# Generated deterministically by seda-macro-lef-normalizer-v1; recipe orfs-ng45-fakeram-metal3-coupledl2-pg-v1.
VERSION 5.8 ;
BUSBITCHARS "[]" ;
DIVIDERCHAR "/" ;

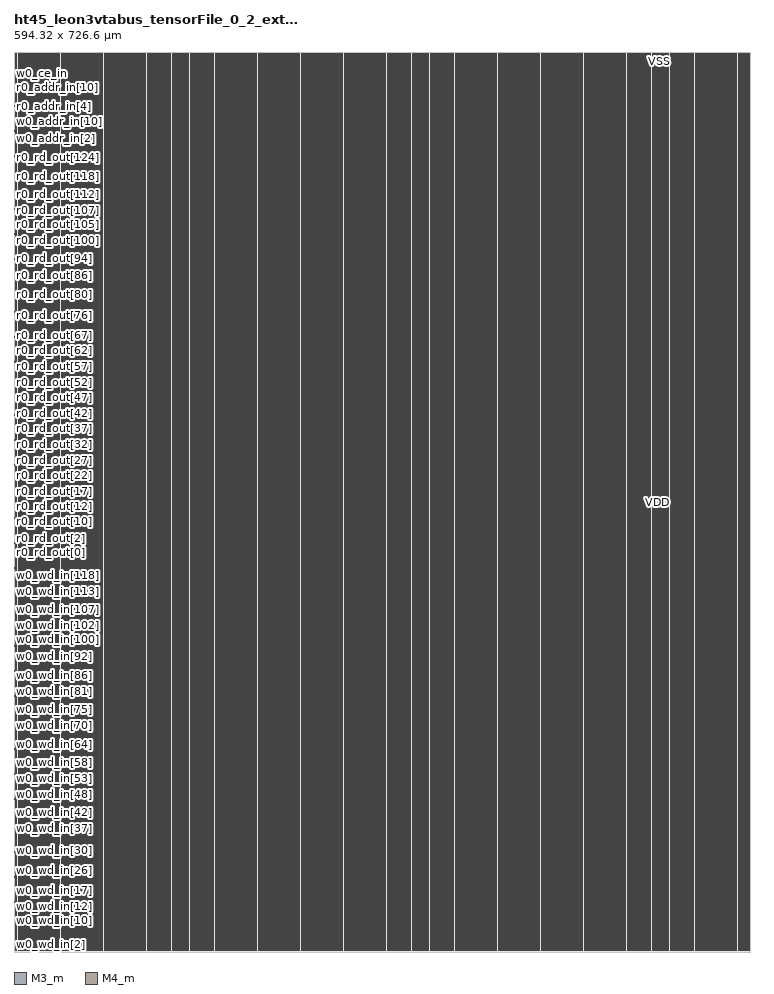
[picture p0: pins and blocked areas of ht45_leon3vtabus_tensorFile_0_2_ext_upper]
MACRO ht45_leon3vtabus_tensorFile_0_2_ext_upper
  FOREIGN ht45_leon3vtabus_tensorFile_0_2_ext_upper 0 0 ;
  CLASS COVER ;
  ORIGIN 0 0 ;
  SIZE 594.32 BY 726.6 ;
  SYMMETRY X Y R90 ;
  PIN w0_wd_in[0]
    DIRECTION INPUT ;
    USE SIGNAL ;
    SHAPE ABUTMENT ;
    PORT
      LAYER M3_m ;
      RECT 0 0.035 0.07 0.105 ;
    END
  END w0_wd_in[0]
  PIN w0_wd_in[1]
    DIRECTION INPUT ;
    USE SIGNAL ;
    SHAPE ABUTMENT ;
    PORT
      LAYER M3_m ;
      RECT 0 2.555 0.07 2.625 ;
    END
  END w0_wd_in[1]
  PIN w0_wd_in[2]
    DIRECTION INPUT ;
    USE SIGNAL ;
    SHAPE ABUTMENT ;
    PORT
      LAYER M3_m ;
      RECT 0 5.075 0.07 5.145 ;
    END
  END w0_wd_in[2]
  PIN w0_wd_in[3]
    DIRECTION INPUT ;
    USE SIGNAL ;
    SHAPE ABUTMENT ;
    PORT
      LAYER M3_m ;
      RECT 0 7.595 0.07 7.665 ;
    END
  END w0_wd_in[3]
  PIN w0_wd_in[4]
    DIRECTION INPUT ;
    USE SIGNAL ;
    SHAPE ABUTMENT ;
    PORT
      LAYER M3_m ;
      RECT 0 10.115 0.07 10.185 ;
    END
  END w0_wd_in[4]
  PIN w0_wd_in[5]
    DIRECTION INPUT ;
    USE SIGNAL ;
    SHAPE ABUTMENT ;
    PORT
      LAYER M3_m ;
      RECT 0 12.635 0.07 12.705 ;
    END
  END w0_wd_in[5]
  PIN w0_wd_in[6]
    DIRECTION INPUT ;
    USE SIGNAL ;
    SHAPE ABUTMENT ;
    PORT
      LAYER M3_m ;
      RECT 0 15.155 0.07 15.225 ;
    END
  END w0_wd_in[6]
  PIN w0_wd_in[7]
    DIRECTION INPUT ;
    USE SIGNAL ;
    SHAPE ABUTMENT ;
    PORT
      LAYER M3_m ;
      RECT 0 17.675 0.07 17.745 ;
    END
  END w0_wd_in[7]
  PIN w0_wd_in[8]
    DIRECTION INPUT ;
    USE SIGNAL ;
    SHAPE ABUTMENT ;
    PORT
      LAYER M3_m ;
      RECT 0 20.195 0.07 20.265 ;
    END
  END w0_wd_in[8]
  PIN w0_wd_in[9]
    DIRECTION INPUT ;
    USE SIGNAL ;
    SHAPE ABUTMENT ;
    PORT
      LAYER M3_m ;
      RECT 0 22.715 0.07 22.785 ;
    END
  END w0_wd_in[9]
  PIN w0_wd_in[10]
    DIRECTION INPUT ;
    USE SIGNAL ;
    SHAPE ABUTMENT ;
    PORT
      LAYER M3_m ;
      RECT 0 25.235 0.07 25.305 ;
    END
  END w0_wd_in[10]
  PIN w0_wd_in[11]
    DIRECTION INPUT ;
    USE SIGNAL ;
    SHAPE ABUTMENT ;
    PORT
      LAYER M3_m ;
      RECT 0 27.755 0.07 27.825 ;
    END
  END w0_wd_in[11]
  PIN w0_wd_in[12]
    DIRECTION INPUT ;
    USE SIGNAL ;
    SHAPE ABUTMENT ;
    PORT
      LAYER M3_m ;
      RECT 0 30.275 0.07 30.345 ;
    END
  END w0_wd_in[12]
  PIN w0_wd_in[13]
    DIRECTION INPUT ;
    USE SIGNAL ;
    SHAPE ABUTMENT ;
    PORT
      LAYER M3_m ;
      RECT 0 32.795 0.07 32.865 ;
    END
  END w0_wd_in[13]
  PIN w0_wd_in[14]
    DIRECTION INPUT ;
    USE SIGNAL ;
    SHAPE ABUTMENT ;
    PORT
      LAYER M3_m ;
      RECT 0 35.315 0.07 35.385 ;
    END
  END w0_wd_in[14]
  PIN w0_wd_in[15]
    DIRECTION INPUT ;
    USE SIGNAL ;
    SHAPE ABUTMENT ;
    PORT
      LAYER M3_m ;
      RECT 0 37.835 0.07 37.905 ;
    END
  END w0_wd_in[15]
  PIN w0_wd_in[16]
    DIRECTION INPUT ;
    USE SIGNAL ;
    SHAPE ABUTMENT ;
    PORT
      LAYER M3_m ;
      RECT 0 40.355 0.07 40.425 ;
    END
  END w0_wd_in[16]
  PIN w0_wd_in[17]
    DIRECTION INPUT ;
    USE SIGNAL ;
    SHAPE ABUTMENT ;
    PORT
      LAYER M3_m ;
      RECT 0 42.875 0.07 42.945 ;
    END
  END w0_wd_in[17]
  PIN w0_wd_in[18]
    DIRECTION INPUT ;
    USE SIGNAL ;
    SHAPE ABUTMENT ;
    PORT
      LAYER M3_m ;
      RECT 0 45.395 0.07 45.465 ;
    END
  END w0_wd_in[18]
  PIN w0_wd_in[19]
    DIRECTION INPUT ;
    USE SIGNAL ;
    SHAPE ABUTMENT ;
    PORT
      LAYER M3_m ;
      RECT 0 47.915 0.07 47.985 ;
    END
  END w0_wd_in[19]
  PIN w0_wd_in[20]
    DIRECTION INPUT ;
    USE SIGNAL ;
    SHAPE ABUTMENT ;
    PORT
      LAYER M3_m ;
      RECT 0 50.435 0.07 50.505 ;
    END
  END w0_wd_in[20]
  PIN w0_wd_in[21]
    DIRECTION INPUT ;
    USE SIGNAL ;
    SHAPE ABUTMENT ;
    PORT
      LAYER M3_m ;
      RECT 0 52.955 0.07 53.025 ;
    END
  END w0_wd_in[21]
  PIN w0_wd_in[22]
    DIRECTION INPUT ;
    USE SIGNAL ;
    SHAPE ABUTMENT ;
    PORT
      LAYER M3_m ;
      RECT 0 55.475 0.07 55.545 ;
    END
  END w0_wd_in[22]
  PIN w0_wd_in[23]
    DIRECTION INPUT ;
    USE SIGNAL ;
    SHAPE ABUTMENT ;
    PORT
      LAYER M3_m ;
      RECT 0 57.995 0.07 58.065 ;
    END
  END w0_wd_in[23]
  PIN w0_wd_in[24]
    DIRECTION INPUT ;
    USE SIGNAL ;
    SHAPE ABUTMENT ;
    PORT
      LAYER M3_m ;
      RECT 0 60.515 0.07 60.585 ;
    END
  END w0_wd_in[24]
  PIN w0_wd_in[25]
    DIRECTION INPUT ;
    USE SIGNAL ;
    SHAPE ABUTMENT ;
    PORT
      LAYER M3_m ;
      RECT 0 63.035 0.07 63.105 ;
    END
  END w0_wd_in[25]
  PIN w0_wd_in[26]
    DIRECTION INPUT ;
    USE SIGNAL ;
    SHAPE ABUTMENT ;
    PORT
      LAYER M3_m ;
      RECT 0 65.555 0.07 65.625 ;
    END
  END w0_wd_in[26]
  PIN w0_wd_in[27]
    DIRECTION INPUT ;
    USE SIGNAL ;
    SHAPE ABUTMENT ;
    PORT
      LAYER M3_m ;
      RECT 0 68.075 0.07 68.145 ;
    END
  END w0_wd_in[27]
  PIN w0_wd_in[28]
    DIRECTION INPUT ;
    USE SIGNAL ;
    SHAPE ABUTMENT ;
    PORT
      LAYER M3_m ;
      RECT 0 70.595 0.07 70.665 ;
    END
  END w0_wd_in[28]
  PIN w0_wd_in[29]
    DIRECTION INPUT ;
    USE SIGNAL ;
    SHAPE ABUTMENT ;
    PORT
      LAYER M3_m ;
      RECT 0 73.115 0.07 73.185 ;
    END
  END w0_wd_in[29]
  PIN w0_wd_in[30]
    DIRECTION INPUT ;
    USE SIGNAL ;
    SHAPE ABUTMENT ;
    PORT
      LAYER M3_m ;
      RECT 0 75.635 0.07 75.705 ;
    END
  END w0_wd_in[30]
  PIN w0_wd_in[31]
    DIRECTION INPUT ;
    USE SIGNAL ;
    SHAPE ABUTMENT ;
    PORT
      LAYER M3_m ;
      RECT 0 78.155 0.07 78.225 ;
    END
  END w0_wd_in[31]
  PIN w0_wd_in[32]
    DIRECTION INPUT ;
    USE SIGNAL ;
    SHAPE ABUTMENT ;
    PORT
      LAYER M3_m ;
      RECT 0 80.675 0.07 80.745 ;
    END
  END w0_wd_in[32]
  PIN w0_wd_in[33]
    DIRECTION INPUT ;
    USE SIGNAL ;
    SHAPE ABUTMENT ;
    PORT
      LAYER M3_m ;
      RECT 0 83.195 0.07 83.265 ;
    END
  END w0_wd_in[33]
  PIN w0_wd_in[34]
    DIRECTION INPUT ;
    USE SIGNAL ;
    SHAPE ABUTMENT ;
    PORT
      LAYER M3_m ;
      RECT 0 85.715 0.07 85.785 ;
    END
  END w0_wd_in[34]
  PIN w0_wd_in[35]
    DIRECTION INPUT ;
    USE SIGNAL ;
    SHAPE ABUTMENT ;
    PORT
      LAYER M3_m ;
      RECT 0 88.235 0.07 88.305 ;
    END
  END w0_wd_in[35]
  PIN w0_wd_in[36]
    DIRECTION INPUT ;
    USE SIGNAL ;
    SHAPE ABUTMENT ;
    PORT
      LAYER M3_m ;
      RECT 0 90.755 0.07 90.825 ;
    END
  END w0_wd_in[36]
  PIN w0_wd_in[37]
    DIRECTION INPUT ;
    USE SIGNAL ;
    SHAPE ABUTMENT ;
    PORT
      LAYER M3_m ;
      RECT 0 93.275 0.07 93.345 ;
    END
  END w0_wd_in[37]
  PIN w0_wd_in[38]
    DIRECTION INPUT ;
    USE SIGNAL ;
    SHAPE ABUTMENT ;
    PORT
      LAYER M3_m ;
      RECT 0 95.795 0.07 95.865 ;
    END
  END w0_wd_in[38]
  PIN w0_wd_in[39]
    DIRECTION INPUT ;
    USE SIGNAL ;
    SHAPE ABUTMENT ;
    PORT
      LAYER M3_m ;
      RECT 0 98.315 0.07 98.385 ;
    END
  END w0_wd_in[39]
  PIN w0_wd_in[40]
    DIRECTION INPUT ;
    USE SIGNAL ;
    SHAPE ABUTMENT ;
    PORT
      LAYER M3_m ;
      RECT 0 100.835 0.07 100.905 ;
    END
  END w0_wd_in[40]
  PIN w0_wd_in[41]
    DIRECTION INPUT ;
    USE SIGNAL ;
    SHAPE ABUTMENT ;
    PORT
      LAYER M3_m ;
      RECT 0 103.355 0.07 103.425 ;
    END
  END w0_wd_in[41]
  PIN w0_wd_in[42]
    DIRECTION INPUT ;
    USE SIGNAL ;
    SHAPE ABUTMENT ;
    PORT
      LAYER M3_m ;
      RECT 0 105.875 0.07 105.945 ;
    END
  END w0_wd_in[42]
  PIN w0_wd_in[43]
    DIRECTION INPUT ;
    USE SIGNAL ;
    SHAPE ABUTMENT ;
    PORT
      LAYER M3_m ;
      RECT 0 108.395 0.07 108.465 ;
    END
  END w0_wd_in[43]
  PIN w0_wd_in[44]
    DIRECTION INPUT ;
    USE SIGNAL ;
    SHAPE ABUTMENT ;
    PORT
      LAYER M3_m ;
      RECT 0 110.915 0.07 110.985 ;
    END
  END w0_wd_in[44]
  PIN w0_wd_in[45]
    DIRECTION INPUT ;
    USE SIGNAL ;
    SHAPE ABUTMENT ;
    PORT
      LAYER M3_m ;
      RECT 0 113.435 0.07 113.505 ;
    END
  END w0_wd_in[45]
  PIN w0_wd_in[46]
    DIRECTION INPUT ;
    USE SIGNAL ;
    SHAPE ABUTMENT ;
    PORT
      LAYER M3_m ;
      RECT 0 115.955 0.07 116.025 ;
    END
  END w0_wd_in[46]
  PIN w0_wd_in[47]
    DIRECTION INPUT ;
    USE SIGNAL ;
    SHAPE ABUTMENT ;
    PORT
      LAYER M3_m ;
      RECT 0 118.475 0.07 118.545 ;
    END
  END w0_wd_in[47]
  PIN w0_wd_in[48]
    DIRECTION INPUT ;
    USE SIGNAL ;
    SHAPE ABUTMENT ;
    PORT
      LAYER M3_m ;
      RECT 0 120.995 0.07 121.065 ;
    END
  END w0_wd_in[48]
  PIN w0_wd_in[49]
    DIRECTION INPUT ;
    USE SIGNAL ;
    SHAPE ABUTMENT ;
    PORT
      LAYER M3_m ;
      RECT 0 123.515 0.07 123.585 ;
    END
  END w0_wd_in[49]
  PIN w0_wd_in[50]
    DIRECTION INPUT ;
    USE SIGNAL ;
    SHAPE ABUTMENT ;
    PORT
      LAYER M3_m ;
      RECT 0 126.035 0.07 126.105 ;
    END
  END w0_wd_in[50]
  PIN w0_wd_in[51]
    DIRECTION INPUT ;
    USE SIGNAL ;
    SHAPE ABUTMENT ;
    PORT
      LAYER M3_m ;
      RECT 0 128.555 0.07 128.625 ;
    END
  END w0_wd_in[51]
  PIN w0_wd_in[52]
    DIRECTION INPUT ;
    USE SIGNAL ;
    SHAPE ABUTMENT ;
    PORT
      LAYER M3_m ;
      RECT 0 131.075 0.07 131.145 ;
    END
  END w0_wd_in[52]
  PIN w0_wd_in[53]
    DIRECTION INPUT ;
    USE SIGNAL ;
    SHAPE ABUTMENT ;
    PORT
      LAYER M3_m ;
      RECT 0 133.595 0.07 133.665 ;
    END
  END w0_wd_in[53]
  PIN w0_wd_in[54]
    DIRECTION INPUT ;
    USE SIGNAL ;
    SHAPE ABUTMENT ;
    PORT
      LAYER M3_m ;
      RECT 0 136.115 0.07 136.185 ;
    END
  END w0_wd_in[54]
  PIN w0_wd_in[55]
    DIRECTION INPUT ;
    USE SIGNAL ;
    SHAPE ABUTMENT ;
    PORT
      LAYER M3_m ;
      RECT 0 138.635 0.07 138.705 ;
    END
  END w0_wd_in[55]
  PIN w0_wd_in[56]
    DIRECTION INPUT ;
    USE SIGNAL ;
    SHAPE ABUTMENT ;
    PORT
      LAYER M3_m ;
      RECT 0 141.155 0.07 141.225 ;
    END
  END w0_wd_in[56]
  PIN w0_wd_in[57]
    DIRECTION INPUT ;
    USE SIGNAL ;
    SHAPE ABUTMENT ;
    PORT
      LAYER M3_m ;
      RECT 0 143.675 0.07 143.745 ;
    END
  END w0_wd_in[57]
  PIN w0_wd_in[58]
    DIRECTION INPUT ;
    USE SIGNAL ;
    SHAPE ABUTMENT ;
    PORT
      LAYER M3_m ;
      RECT 0 146.195 0.07 146.265 ;
    END
  END w0_wd_in[58]
  PIN w0_wd_in[59]
    DIRECTION INPUT ;
    USE SIGNAL ;
    SHAPE ABUTMENT ;
    PORT
      LAYER M3_m ;
      RECT 0 148.715 0.07 148.785 ;
    END
  END w0_wd_in[59]
  PIN w0_wd_in[60]
    DIRECTION INPUT ;
    USE SIGNAL ;
    SHAPE ABUTMENT ;
    PORT
      LAYER M3_m ;
      RECT 0 151.235 0.07 151.305 ;
    END
  END w0_wd_in[60]
  PIN w0_wd_in[61]
    DIRECTION INPUT ;
    USE SIGNAL ;
    SHAPE ABUTMENT ;
    PORT
      LAYER M3_m ;
      RECT 0 153.755 0.07 153.825 ;
    END
  END w0_wd_in[61]
  PIN w0_wd_in[62]
    DIRECTION INPUT ;
    USE SIGNAL ;
    SHAPE ABUTMENT ;
    PORT
      LAYER M3_m ;
      RECT 0 156.275 0.07 156.345 ;
    END
  END w0_wd_in[62]
  PIN w0_wd_in[63]
    DIRECTION INPUT ;
    USE SIGNAL ;
    SHAPE ABUTMENT ;
    PORT
      LAYER M3_m ;
      RECT 0 158.795 0.07 158.865 ;
    END
  END w0_wd_in[63]
  PIN w0_wd_in[64]
    DIRECTION INPUT ;
    USE SIGNAL ;
    SHAPE ABUTMENT ;
    PORT
      LAYER M3_m ;
      RECT 0 161.315 0.07 161.385 ;
    END
  END w0_wd_in[64]
  PIN w0_wd_in[65]
    DIRECTION INPUT ;
    USE SIGNAL ;
    SHAPE ABUTMENT ;
    PORT
      LAYER M3_m ;
      RECT 0 163.835 0.07 163.905 ;
    END
  END w0_wd_in[65]
  PIN w0_wd_in[66]
    DIRECTION INPUT ;
    USE SIGNAL ;
    SHAPE ABUTMENT ;
    PORT
      LAYER M3_m ;
      RECT 0 166.355 0.07 166.425 ;
    END
  END w0_wd_in[66]
  PIN w0_wd_in[67]
    DIRECTION INPUT ;
    USE SIGNAL ;
    SHAPE ABUTMENT ;
    PORT
      LAYER M3_m ;
      RECT 0 168.875 0.07 168.945 ;
    END
  END w0_wd_in[67]
  PIN w0_wd_in[68]
    DIRECTION INPUT ;
    USE SIGNAL ;
    SHAPE ABUTMENT ;
    PORT
      LAYER M3_m ;
      RECT 0 171.395 0.07 171.465 ;
    END
  END w0_wd_in[68]
  PIN w0_wd_in[69]
    DIRECTION INPUT ;
    USE SIGNAL ;
    SHAPE ABUTMENT ;
    PORT
      LAYER M3_m ;
      RECT 0 173.915 0.07 173.985 ;
    END
  END w0_wd_in[69]
  PIN w0_wd_in[70]
    DIRECTION INPUT ;
    USE SIGNAL ;
    SHAPE ABUTMENT ;
    PORT
      LAYER M3_m ;
      RECT 0 176.435 0.07 176.505 ;
    END
  END w0_wd_in[70]
  PIN w0_wd_in[71]
    DIRECTION INPUT ;
    USE SIGNAL ;
    SHAPE ABUTMENT ;
    PORT
      LAYER M3_m ;
      RECT 0 178.955 0.07 179.025 ;
    END
  END w0_wd_in[71]
  PIN w0_wd_in[72]
    DIRECTION INPUT ;
    USE SIGNAL ;
    SHAPE ABUTMENT ;
    PORT
      LAYER M3_m ;
      RECT 0 181.475 0.07 181.545 ;
    END
  END w0_wd_in[72]
  PIN w0_wd_in[73]
    DIRECTION INPUT ;
    USE SIGNAL ;
    SHAPE ABUTMENT ;
    PORT
      LAYER M3_m ;
      RECT 0 183.995 0.07 184.065 ;
    END
  END w0_wd_in[73]
  PIN w0_wd_in[74]
    DIRECTION INPUT ;
    USE SIGNAL ;
    SHAPE ABUTMENT ;
    PORT
      LAYER M3_m ;
      RECT 0 186.515 0.07 186.585 ;
    END
  END w0_wd_in[74]
  PIN w0_wd_in[75]
    DIRECTION INPUT ;
    USE SIGNAL ;
    SHAPE ABUTMENT ;
    PORT
      LAYER M3_m ;
      RECT 0 189.035 0.07 189.105 ;
    END
  END w0_wd_in[75]
  PIN w0_wd_in[76]
    DIRECTION INPUT ;
    USE SIGNAL ;
    SHAPE ABUTMENT ;
    PORT
      LAYER M3_m ;
      RECT 0 191.555 0.07 191.625 ;
    END
  END w0_wd_in[76]
  PIN w0_wd_in[77]
    DIRECTION INPUT ;
    USE SIGNAL ;
    SHAPE ABUTMENT ;
    PORT
      LAYER M3_m ;
      RECT 0 194.075 0.07 194.145 ;
    END
  END w0_wd_in[77]
  PIN w0_wd_in[78]
    DIRECTION INPUT ;
    USE SIGNAL ;
    SHAPE ABUTMENT ;
    PORT
      LAYER M3_m ;
      RECT 0 196.595 0.07 196.665 ;
    END
  END w0_wd_in[78]
  PIN w0_wd_in[79]
    DIRECTION INPUT ;
    USE SIGNAL ;
    SHAPE ABUTMENT ;
    PORT
      LAYER M3_m ;
      RECT 0 199.115 0.07 199.185 ;
    END
  END w0_wd_in[79]
  PIN w0_wd_in[80]
    DIRECTION INPUT ;
    USE SIGNAL ;
    SHAPE ABUTMENT ;
    PORT
      LAYER M3_m ;
      RECT 0 201.635 0.07 201.705 ;
    END
  END w0_wd_in[80]
  PIN w0_wd_in[81]
    DIRECTION INPUT ;
    USE SIGNAL ;
    SHAPE ABUTMENT ;
    PORT
      LAYER M3_m ;
      RECT 0 204.155 0.07 204.225 ;
    END
  END w0_wd_in[81]
  PIN w0_wd_in[82]
    DIRECTION INPUT ;
    USE SIGNAL ;
    SHAPE ABUTMENT ;
    PORT
      LAYER M3_m ;
      RECT 0 206.675 0.07 206.745 ;
    END
  END w0_wd_in[82]
  PIN w0_wd_in[83]
    DIRECTION INPUT ;
    USE SIGNAL ;
    SHAPE ABUTMENT ;
    PORT
      LAYER M3_m ;
      RECT 0 209.195 0.07 209.265 ;
    END
  END w0_wd_in[83]
  PIN w0_wd_in[84]
    DIRECTION INPUT ;
    USE SIGNAL ;
    SHAPE ABUTMENT ;
    PORT
      LAYER M3_m ;
      RECT 0 211.715 0.07 211.785 ;
    END
  END w0_wd_in[84]
  PIN w0_wd_in[85]
    DIRECTION INPUT ;
    USE SIGNAL ;
    SHAPE ABUTMENT ;
    PORT
      LAYER M3_m ;
      RECT 0 214.235 0.07 214.305 ;
    END
  END w0_wd_in[85]
  PIN w0_wd_in[86]
    DIRECTION INPUT ;
    USE SIGNAL ;
    SHAPE ABUTMENT ;
    PORT
      LAYER M3_m ;
      RECT 0 216.755 0.07 216.825 ;
    END
  END w0_wd_in[86]
  PIN w0_wd_in[87]
    DIRECTION INPUT ;
    USE SIGNAL ;
    SHAPE ABUTMENT ;
    PORT
      LAYER M3_m ;
      RECT 0 219.275 0.07 219.345 ;
    END
  END w0_wd_in[87]
  PIN w0_wd_in[88]
    DIRECTION INPUT ;
    USE SIGNAL ;
    SHAPE ABUTMENT ;
    PORT
      LAYER M3_m ;
      RECT 0 221.795 0.07 221.865 ;
    END
  END w0_wd_in[88]
  PIN w0_wd_in[89]
    DIRECTION INPUT ;
    USE SIGNAL ;
    SHAPE ABUTMENT ;
    PORT
      LAYER M3_m ;
      RECT 0 224.315 0.07 224.385 ;
    END
  END w0_wd_in[89]
  PIN w0_wd_in[90]
    DIRECTION INPUT ;
    USE SIGNAL ;
    SHAPE ABUTMENT ;
    PORT
      LAYER M3_m ;
      RECT 0 226.835 0.07 226.905 ;
    END
  END w0_wd_in[90]
  PIN w0_wd_in[91]
    DIRECTION INPUT ;
    USE SIGNAL ;
    SHAPE ABUTMENT ;
    PORT
      LAYER M3_m ;
      RECT 0 229.355 0.07 229.425 ;
    END
  END w0_wd_in[91]
  PIN w0_wd_in[92]
    DIRECTION INPUT ;
    USE SIGNAL ;
    SHAPE ABUTMENT ;
    PORT
      LAYER M3_m ;
      RECT 0 231.875 0.07 231.945 ;
    END
  END w0_wd_in[92]
  PIN w0_wd_in[93]
    DIRECTION INPUT ;
    USE SIGNAL ;
    SHAPE ABUTMENT ;
    PORT
      LAYER M3_m ;
      RECT 0 234.395 0.07 234.465 ;
    END
  END w0_wd_in[93]
  PIN w0_wd_in[94]
    DIRECTION INPUT ;
    USE SIGNAL ;
    SHAPE ABUTMENT ;
    PORT
      LAYER M3_m ;
      RECT 0 236.915 0.07 236.985 ;
    END
  END w0_wd_in[94]
  PIN w0_wd_in[95]
    DIRECTION INPUT ;
    USE SIGNAL ;
    SHAPE ABUTMENT ;
    PORT
      LAYER M3_m ;
      RECT 0 239.435 0.07 239.505 ;
    END
  END w0_wd_in[95]
  PIN w0_wd_in[96]
    DIRECTION INPUT ;
    USE SIGNAL ;
    SHAPE ABUTMENT ;
    PORT
      LAYER M3_m ;
      RECT 0 241.955 0.07 242.025 ;
    END
  END w0_wd_in[96]
  PIN w0_wd_in[97]
    DIRECTION INPUT ;
    USE SIGNAL ;
    SHAPE ABUTMENT ;
    PORT
      LAYER M3_m ;
      RECT 0 244.475 0.07 244.545 ;
    END
  END w0_wd_in[97]
  PIN w0_wd_in[98]
    DIRECTION INPUT ;
    USE SIGNAL ;
    SHAPE ABUTMENT ;
    PORT
      LAYER M3_m ;
      RECT 0 246.995 0.07 247.065 ;
    END
  END w0_wd_in[98]
  PIN w0_wd_in[99]
    DIRECTION INPUT ;
    USE SIGNAL ;
    SHAPE ABUTMENT ;
    PORT
      LAYER M3_m ;
      RECT 0 249.515 0.07 249.585 ;
    END
  END w0_wd_in[99]
  PIN w0_wd_in[100]
    DIRECTION INPUT ;
    USE SIGNAL ;
    SHAPE ABUTMENT ;
    PORT
      LAYER M3_m ;
      RECT 0 252.035 0.07 252.105 ;
    END
  END w0_wd_in[100]
  PIN w0_wd_in[101]
    DIRECTION INPUT ;
    USE SIGNAL ;
    SHAPE ABUTMENT ;
    PORT
      LAYER M3_m ;
      RECT 0 254.555 0.07 254.625 ;
    END
  END w0_wd_in[101]
  PIN w0_wd_in[102]
    DIRECTION INPUT ;
    USE SIGNAL ;
    SHAPE ABUTMENT ;
    PORT
      LAYER M3_m ;
      RECT 0 257.075 0.07 257.145 ;
    END
  END w0_wd_in[102]
  PIN w0_wd_in[103]
    DIRECTION INPUT ;
    USE SIGNAL ;
    SHAPE ABUTMENT ;
    PORT
      LAYER M3_m ;
      RECT 0 259.595 0.07 259.665 ;
    END
  END w0_wd_in[103]
  PIN w0_wd_in[104]
    DIRECTION INPUT ;
    USE SIGNAL ;
    SHAPE ABUTMENT ;
    PORT
      LAYER M3_m ;
      RECT 0 262.115 0.07 262.185 ;
    END
  END w0_wd_in[104]
  PIN w0_wd_in[105]
    DIRECTION INPUT ;
    USE SIGNAL ;
    SHAPE ABUTMENT ;
    PORT
      LAYER M3_m ;
      RECT 0 264.635 0.07 264.705 ;
    END
  END w0_wd_in[105]
  PIN w0_wd_in[106]
    DIRECTION INPUT ;
    USE SIGNAL ;
    SHAPE ABUTMENT ;
    PORT
      LAYER M3_m ;
      RECT 0 267.155 0.07 267.225 ;
    END
  END w0_wd_in[106]
  PIN w0_wd_in[107]
    DIRECTION INPUT ;
    USE SIGNAL ;
    SHAPE ABUTMENT ;
    PORT
      LAYER M3_m ;
      RECT 0 269.675 0.07 269.745 ;
    END
  END w0_wd_in[107]
  PIN w0_wd_in[108]
    DIRECTION INPUT ;
    USE SIGNAL ;
    SHAPE ABUTMENT ;
    PORT
      LAYER M3_m ;
      RECT 0 272.195 0.07 272.265 ;
    END
  END w0_wd_in[108]
  PIN w0_wd_in[109]
    DIRECTION INPUT ;
    USE SIGNAL ;
    SHAPE ABUTMENT ;
    PORT
      LAYER M3_m ;
      RECT 0 274.715 0.07 274.785 ;
    END
  END w0_wd_in[109]
  PIN w0_wd_in[110]
    DIRECTION INPUT ;
    USE SIGNAL ;
    SHAPE ABUTMENT ;
    PORT
      LAYER M3_m ;
      RECT 0 277.235 0.07 277.305 ;
    END
  END w0_wd_in[110]
  PIN w0_wd_in[111]
    DIRECTION INPUT ;
    USE SIGNAL ;
    SHAPE ABUTMENT ;
    PORT
      LAYER M3_m ;
      RECT 0 279.755 0.07 279.825 ;
    END
  END w0_wd_in[111]
  PIN w0_wd_in[112]
    DIRECTION INPUT ;
    USE SIGNAL ;
    SHAPE ABUTMENT ;
    PORT
      LAYER M3_m ;
      RECT 0 282.275 0.07 282.345 ;
    END
  END w0_wd_in[112]
  PIN w0_wd_in[113]
    DIRECTION INPUT ;
    USE SIGNAL ;
    SHAPE ABUTMENT ;
    PORT
      LAYER M3_m ;
      RECT 0 284.795 0.07 284.865 ;
    END
  END w0_wd_in[113]
  PIN w0_wd_in[114]
    DIRECTION INPUT ;
    USE SIGNAL ;
    SHAPE ABUTMENT ;
    PORT
      LAYER M3_m ;
      RECT 0 287.315 0.07 287.385 ;
    END
  END w0_wd_in[114]
  PIN w0_wd_in[115]
    DIRECTION INPUT ;
    USE SIGNAL ;
    SHAPE ABUTMENT ;
    PORT
      LAYER M3_m ;
      RECT 0 289.835 0.07 289.905 ;
    END
  END w0_wd_in[115]
  PIN w0_wd_in[116]
    DIRECTION INPUT ;
    USE SIGNAL ;
    SHAPE ABUTMENT ;
    PORT
      LAYER M3_m ;
      RECT 0 292.355 0.07 292.425 ;
    END
  END w0_wd_in[116]
  PIN w0_wd_in[117]
    DIRECTION INPUT ;
    USE SIGNAL ;
    SHAPE ABUTMENT ;
    PORT
      LAYER M3_m ;
      RECT 0 294.875 0.07 294.945 ;
    END
  END w0_wd_in[117]
  PIN w0_wd_in[118]
    DIRECTION INPUT ;
    USE SIGNAL ;
    SHAPE ABUTMENT ;
    PORT
      LAYER M3_m ;
      RECT 0 297.395 0.07 297.465 ;
    END
  END w0_wd_in[118]
  PIN w0_wd_in[119]
    DIRECTION INPUT ;
    USE SIGNAL ;
    SHAPE ABUTMENT ;
    PORT
      LAYER M3_m ;
      RECT 0 299.915 0.07 299.985 ;
    END
  END w0_wd_in[119]
  PIN w0_wd_in[120]
    DIRECTION INPUT ;
    USE SIGNAL ;
    SHAPE ABUTMENT ;
    PORT
      LAYER M3_m ;
      RECT 0 302.435 0.07 302.505 ;
    END
  END w0_wd_in[120]
  PIN w0_wd_in[121]
    DIRECTION INPUT ;
    USE SIGNAL ;
    SHAPE ABUTMENT ;
    PORT
      LAYER M3_m ;
      RECT 0 304.955 0.07 305.025 ;
    END
  END w0_wd_in[121]
  PIN w0_wd_in[122]
    DIRECTION INPUT ;
    USE SIGNAL ;
    SHAPE ABUTMENT ;
    PORT
      LAYER M3_m ;
      RECT 0 307.475 0.07 307.545 ;
    END
  END w0_wd_in[122]
  PIN w0_wd_in[123]
    DIRECTION INPUT ;
    USE SIGNAL ;
    SHAPE ABUTMENT ;
    PORT
      LAYER M3_m ;
      RECT 0 309.995 0.07 310.065 ;
    END
  END w0_wd_in[123]
  PIN w0_wd_in[124]
    DIRECTION INPUT ;
    USE SIGNAL ;
    SHAPE ABUTMENT ;
    PORT
      LAYER M3_m ;
      RECT 0 312.515 0.07 312.585 ;
    END
  END w0_wd_in[124]
  PIN w0_wd_in[125]
    DIRECTION INPUT ;
    USE SIGNAL ;
    SHAPE ABUTMENT ;
    PORT
      LAYER M3_m ;
      RECT 0 315.035 0.07 315.105 ;
    END
  END w0_wd_in[125]
  PIN w0_wd_in[126]
    DIRECTION INPUT ;
    USE SIGNAL ;
    SHAPE ABUTMENT ;
    PORT
      LAYER M3_m ;
      RECT 0 317.555 0.07 317.625 ;
    END
  END w0_wd_in[126]
  PIN w0_wd_in[127]
    DIRECTION INPUT ;
    USE SIGNAL ;
    SHAPE ABUTMENT ;
    PORT
      LAYER M3_m ;
      RECT 0 320.075 0.07 320.145 ;
    END
  END w0_wd_in[127]
  PIN r0_rd_out[0]
    DIRECTION OUTPUT ;
    USE SIGNAL ;
    SHAPE ABUTMENT ;
    PORT
      LAYER M3_m ;
      RECT 0 322.595 0.07 322.665 ;
    END
  END r0_rd_out[0]
  PIN r0_rd_out[1]
    DIRECTION OUTPUT ;
    USE SIGNAL ;
    SHAPE ABUTMENT ;
    PORT
      LAYER M3_m ;
      RECT 0 325.115 0.07 325.185 ;
    END
  END r0_rd_out[1]
  PIN r0_rd_out[2]
    DIRECTION OUTPUT ;
    USE SIGNAL ;
    SHAPE ABUTMENT ;
    PORT
      LAYER M3_m ;
      RECT 0 327.635 0.07 327.705 ;
    END
  END r0_rd_out[2]
  PIN r0_rd_out[3]
    DIRECTION OUTPUT ;
    USE SIGNAL ;
    SHAPE ABUTMENT ;
    PORT
      LAYER M3_m ;
      RECT 0 330.155 0.07 330.225 ;
    END
  END r0_rd_out[3]
  PIN r0_rd_out[4]
    DIRECTION OUTPUT ;
    USE SIGNAL ;
    SHAPE ABUTMENT ;
    PORT
      LAYER M3_m ;
      RECT 0 332.675 0.07 332.745 ;
    END
  END r0_rd_out[4]
  PIN r0_rd_out[5]
    DIRECTION OUTPUT ;
    USE SIGNAL ;
    SHAPE ABUTMENT ;
    PORT
      LAYER M3_m ;
      RECT 0 335.195 0.07 335.265 ;
    END
  END r0_rd_out[5]
  PIN r0_rd_out[6]
    DIRECTION OUTPUT ;
    USE SIGNAL ;
    SHAPE ABUTMENT ;
    PORT
      LAYER M3_m ;
      RECT 0 337.715 0.07 337.785 ;
    END
  END r0_rd_out[6]
  PIN r0_rd_out[7]
    DIRECTION OUTPUT ;
    USE SIGNAL ;
    SHAPE ABUTMENT ;
    PORT
      LAYER M3_m ;
      RECT 0 340.235 0.07 340.305 ;
    END
  END r0_rd_out[7]
  PIN r0_rd_out[8]
    DIRECTION OUTPUT ;
    USE SIGNAL ;
    SHAPE ABUTMENT ;
    PORT
      LAYER M3_m ;
      RECT 0 342.755 0.07 342.825 ;
    END
  END r0_rd_out[8]
  PIN r0_rd_out[9]
    DIRECTION OUTPUT ;
    USE SIGNAL ;
    SHAPE ABUTMENT ;
    PORT
      LAYER M3_m ;
      RECT 0 345.275 0.07 345.345 ;
    END
  END r0_rd_out[9]
  PIN r0_rd_out[10]
    DIRECTION OUTPUT ;
    USE SIGNAL ;
    SHAPE ABUTMENT ;
    PORT
      LAYER M3_m ;
      RECT 0 347.795 0.07 347.865 ;
    END
  END r0_rd_out[10]
  PIN r0_rd_out[11]
    DIRECTION OUTPUT ;
    USE SIGNAL ;
    SHAPE ABUTMENT ;
    PORT
      LAYER M3_m ;
      RECT 0 350.315 0.07 350.385 ;
    END
  END r0_rd_out[11]
  PIN r0_rd_out[12]
    DIRECTION OUTPUT ;
    USE SIGNAL ;
    SHAPE ABUTMENT ;
    PORT
      LAYER M3_m ;
      RECT 0 352.835 0.07 352.905 ;
    END
  END r0_rd_out[12]
  PIN r0_rd_out[13]
    DIRECTION OUTPUT ;
    USE SIGNAL ;
    SHAPE ABUTMENT ;
    PORT
      LAYER M3_m ;
      RECT 0 355.355 0.07 355.425 ;
    END
  END r0_rd_out[13]
  PIN r0_rd_out[14]
    DIRECTION OUTPUT ;
    USE SIGNAL ;
    SHAPE ABUTMENT ;
    PORT
      LAYER M3_m ;
      RECT 0 357.875 0.07 357.945 ;
    END
  END r0_rd_out[14]
  PIN r0_rd_out[15]
    DIRECTION OUTPUT ;
    USE SIGNAL ;
    SHAPE ABUTMENT ;
    PORT
      LAYER M3_m ;
      RECT 0 360.395 0.07 360.465 ;
    END
  END r0_rd_out[15]
  PIN r0_rd_out[16]
    DIRECTION OUTPUT ;
    USE SIGNAL ;
    SHAPE ABUTMENT ;
    PORT
      LAYER M3_m ;
      RECT 0 362.915 0.07 362.985 ;
    END
  END r0_rd_out[16]
  PIN r0_rd_out[17]
    DIRECTION OUTPUT ;
    USE SIGNAL ;
    SHAPE ABUTMENT ;
    PORT
      LAYER M3_m ;
      RECT 0 365.435 0.07 365.505 ;
    END
  END r0_rd_out[17]
  PIN r0_rd_out[18]
    DIRECTION OUTPUT ;
    USE SIGNAL ;
    SHAPE ABUTMENT ;
    PORT
      LAYER M3_m ;
      RECT 0 367.955 0.07 368.025 ;
    END
  END r0_rd_out[18]
  PIN r0_rd_out[19]
    DIRECTION OUTPUT ;
    USE SIGNAL ;
    SHAPE ABUTMENT ;
    PORT
      LAYER M3_m ;
      RECT 0 370.475 0.07 370.545 ;
    END
  END r0_rd_out[19]
  PIN r0_rd_out[20]
    DIRECTION OUTPUT ;
    USE SIGNAL ;
    SHAPE ABUTMENT ;
    PORT
      LAYER M3_m ;
      RECT 0 372.995 0.07 373.065 ;
    END
  END r0_rd_out[20]
  PIN r0_rd_out[21]
    DIRECTION OUTPUT ;
    USE SIGNAL ;
    SHAPE ABUTMENT ;
    PORT
      LAYER M3_m ;
      RECT 0 375.515 0.07 375.585 ;
    END
  END r0_rd_out[21]
  PIN r0_rd_out[22]
    DIRECTION OUTPUT ;
    USE SIGNAL ;
    SHAPE ABUTMENT ;
    PORT
      LAYER M3_m ;
      RECT 0 378.035 0.07 378.105 ;
    END
  END r0_rd_out[22]
  PIN r0_rd_out[23]
    DIRECTION OUTPUT ;
    USE SIGNAL ;
    SHAPE ABUTMENT ;
    PORT
      LAYER M3_m ;
      RECT 0 380.555 0.07 380.625 ;
    END
  END r0_rd_out[23]
  PIN r0_rd_out[24]
    DIRECTION OUTPUT ;
    USE SIGNAL ;
    SHAPE ABUTMENT ;
    PORT
      LAYER M3_m ;
      RECT 0 383.075 0.07 383.145 ;
    END
  END r0_rd_out[24]
  PIN r0_rd_out[25]
    DIRECTION OUTPUT ;
    USE SIGNAL ;
    SHAPE ABUTMENT ;
    PORT
      LAYER M3_m ;
      RECT 0 385.595 0.07 385.665 ;
    END
  END r0_rd_out[25]
  PIN r0_rd_out[26]
    DIRECTION OUTPUT ;
    USE SIGNAL ;
    SHAPE ABUTMENT ;
    PORT
      LAYER M3_m ;
      RECT 0 388.115 0.07 388.185 ;
    END
  END r0_rd_out[26]
  PIN r0_rd_out[27]
    DIRECTION OUTPUT ;
    USE SIGNAL ;
    SHAPE ABUTMENT ;
    PORT
      LAYER M3_m ;
      RECT 0 390.635 0.07 390.705 ;
    END
  END r0_rd_out[27]
  PIN r0_rd_out[28]
    DIRECTION OUTPUT ;
    USE SIGNAL ;
    SHAPE ABUTMENT ;
    PORT
      LAYER M3_m ;
      RECT 0 393.155 0.07 393.225 ;
    END
  END r0_rd_out[28]
  PIN r0_rd_out[29]
    DIRECTION OUTPUT ;
    USE SIGNAL ;
    SHAPE ABUTMENT ;
    PORT
      LAYER M3_m ;
      RECT 0 395.675 0.07 395.745 ;
    END
  END r0_rd_out[29]
  PIN r0_rd_out[30]
    DIRECTION OUTPUT ;
    USE SIGNAL ;
    SHAPE ABUTMENT ;
    PORT
      LAYER M3_m ;
      RECT 0 398.195 0.07 398.265 ;
    END
  END r0_rd_out[30]
  PIN r0_rd_out[31]
    DIRECTION OUTPUT ;
    USE SIGNAL ;
    SHAPE ABUTMENT ;
    PORT
      LAYER M3_m ;
      RECT 0 400.715 0.07 400.785 ;
    END
  END r0_rd_out[31]
  PIN r0_rd_out[32]
    DIRECTION OUTPUT ;
    USE SIGNAL ;
    SHAPE ABUTMENT ;
    PORT
      LAYER M3_m ;
      RECT 0 403.235 0.07 403.305 ;
    END
  END r0_rd_out[32]
  PIN r0_rd_out[33]
    DIRECTION OUTPUT ;
    USE SIGNAL ;
    SHAPE ABUTMENT ;
    PORT
      LAYER M3_m ;
      RECT 0 405.755 0.07 405.825 ;
    END
  END r0_rd_out[33]
  PIN r0_rd_out[34]
    DIRECTION OUTPUT ;
    USE SIGNAL ;
    SHAPE ABUTMENT ;
    PORT
      LAYER M3_m ;
      RECT 0 408.275 0.07 408.345 ;
    END
  END r0_rd_out[34]
  PIN r0_rd_out[35]
    DIRECTION OUTPUT ;
    USE SIGNAL ;
    SHAPE ABUTMENT ;
    PORT
      LAYER M3_m ;
      RECT 0 410.795 0.07 410.865 ;
    END
  END r0_rd_out[35]
  PIN r0_rd_out[36]
    DIRECTION OUTPUT ;
    USE SIGNAL ;
    SHAPE ABUTMENT ;
    PORT
      LAYER M3_m ;
      RECT 0 413.315 0.07 413.385 ;
    END
  END r0_rd_out[36]
  PIN r0_rd_out[37]
    DIRECTION OUTPUT ;
    USE SIGNAL ;
    SHAPE ABUTMENT ;
    PORT
      LAYER M3_m ;
      RECT 0 415.835 0.07 415.905 ;
    END
  END r0_rd_out[37]
  PIN r0_rd_out[38]
    DIRECTION OUTPUT ;
    USE SIGNAL ;
    SHAPE ABUTMENT ;
    PORT
      LAYER M3_m ;
      RECT 0 418.355 0.07 418.425 ;
    END
  END r0_rd_out[38]
  PIN r0_rd_out[39]
    DIRECTION OUTPUT ;
    USE SIGNAL ;
    SHAPE ABUTMENT ;
    PORT
      LAYER M3_m ;
      RECT 0 420.875 0.07 420.945 ;
    END
  END r0_rd_out[39]
  PIN r0_rd_out[40]
    DIRECTION OUTPUT ;
    USE SIGNAL ;
    SHAPE ABUTMENT ;
    PORT
      LAYER M3_m ;
      RECT 0 423.395 0.07 423.465 ;
    END
  END r0_rd_out[40]
  PIN r0_rd_out[41]
    DIRECTION OUTPUT ;
    USE SIGNAL ;
    SHAPE ABUTMENT ;
    PORT
      LAYER M3_m ;
      RECT 0 425.915 0.07 425.985 ;
    END
  END r0_rd_out[41]
  PIN r0_rd_out[42]
    DIRECTION OUTPUT ;
    USE SIGNAL ;
    SHAPE ABUTMENT ;
    PORT
      LAYER M3_m ;
      RECT 0 428.435 0.07 428.505 ;
    END
  END r0_rd_out[42]
  PIN r0_rd_out[43]
    DIRECTION OUTPUT ;
    USE SIGNAL ;
    SHAPE ABUTMENT ;
    PORT
      LAYER M3_m ;
      RECT 0 430.955 0.07 431.025 ;
    END
  END r0_rd_out[43]
  PIN r0_rd_out[44]
    DIRECTION OUTPUT ;
    USE SIGNAL ;
    SHAPE ABUTMENT ;
    PORT
      LAYER M3_m ;
      RECT 0 433.475 0.07 433.545 ;
    END
  END r0_rd_out[44]
  PIN r0_rd_out[45]
    DIRECTION OUTPUT ;
    USE SIGNAL ;
    SHAPE ABUTMENT ;
    PORT
      LAYER M3_m ;
      RECT 0 435.995 0.07 436.065 ;
    END
  END r0_rd_out[45]
  PIN r0_rd_out[46]
    DIRECTION OUTPUT ;
    USE SIGNAL ;
    SHAPE ABUTMENT ;
    PORT
      LAYER M3_m ;
      RECT 0 438.515 0.07 438.585 ;
    END
  END r0_rd_out[46]
  PIN r0_rd_out[47]
    DIRECTION OUTPUT ;
    USE SIGNAL ;
    SHAPE ABUTMENT ;
    PORT
      LAYER M3_m ;
      RECT 0 441.035 0.07 441.105 ;
    END
  END r0_rd_out[47]
  PIN r0_rd_out[48]
    DIRECTION OUTPUT ;
    USE SIGNAL ;
    SHAPE ABUTMENT ;
    PORT
      LAYER M3_m ;
      RECT 0 443.555 0.07 443.625 ;
    END
  END r0_rd_out[48]
  PIN r0_rd_out[49]
    DIRECTION OUTPUT ;
    USE SIGNAL ;
    SHAPE ABUTMENT ;
    PORT
      LAYER M3_m ;
      RECT 0 446.075 0.07 446.145 ;
    END
  END r0_rd_out[49]
  PIN r0_rd_out[50]
    DIRECTION OUTPUT ;
    USE SIGNAL ;
    SHAPE ABUTMENT ;
    PORT
      LAYER M3_m ;
      RECT 0 448.595 0.07 448.665 ;
    END
  END r0_rd_out[50]
  PIN r0_rd_out[51]
    DIRECTION OUTPUT ;
    USE SIGNAL ;
    SHAPE ABUTMENT ;
    PORT
      LAYER M3_m ;
      RECT 0 451.115 0.07 451.185 ;
    END
  END r0_rd_out[51]
  PIN r0_rd_out[52]
    DIRECTION OUTPUT ;
    USE SIGNAL ;
    SHAPE ABUTMENT ;
    PORT
      LAYER M3_m ;
      RECT 0 453.635 0.07 453.705 ;
    END
  END r0_rd_out[52]
  PIN r0_rd_out[53]
    DIRECTION OUTPUT ;
    USE SIGNAL ;
    SHAPE ABUTMENT ;
    PORT
      LAYER M3_m ;
      RECT 0 456.155 0.07 456.225 ;
    END
  END r0_rd_out[53]
  PIN r0_rd_out[54]
    DIRECTION OUTPUT ;
    USE SIGNAL ;
    SHAPE ABUTMENT ;
    PORT
      LAYER M3_m ;
      RECT 0 458.675 0.07 458.745 ;
    END
  END r0_rd_out[54]
  PIN r0_rd_out[55]
    DIRECTION OUTPUT ;
    USE SIGNAL ;
    SHAPE ABUTMENT ;
    PORT
      LAYER M3_m ;
      RECT 0 461.195 0.07 461.265 ;
    END
  END r0_rd_out[55]
  PIN r0_rd_out[56]
    DIRECTION OUTPUT ;
    USE SIGNAL ;
    SHAPE ABUTMENT ;
    PORT
      LAYER M3_m ;
      RECT 0 463.715 0.07 463.785 ;
    END
  END r0_rd_out[56]
  PIN r0_rd_out[57]
    DIRECTION OUTPUT ;
    USE SIGNAL ;
    SHAPE ABUTMENT ;
    PORT
      LAYER M3_m ;
      RECT 0 466.235 0.07 466.305 ;
    END
  END r0_rd_out[57]
  PIN r0_rd_out[58]
    DIRECTION OUTPUT ;
    USE SIGNAL ;
    SHAPE ABUTMENT ;
    PORT
      LAYER M3_m ;
      RECT 0 468.755 0.07 468.825 ;
    END
  END r0_rd_out[58]
  PIN r0_rd_out[59]
    DIRECTION OUTPUT ;
    USE SIGNAL ;
    SHAPE ABUTMENT ;
    PORT
      LAYER M3_m ;
      RECT 0 471.275 0.07 471.345 ;
    END
  END r0_rd_out[59]
  PIN r0_rd_out[60]
    DIRECTION OUTPUT ;
    USE SIGNAL ;
    SHAPE ABUTMENT ;
    PORT
      LAYER M3_m ;
      RECT 0 473.795 0.07 473.865 ;
    END
  END r0_rd_out[60]
  PIN r0_rd_out[61]
    DIRECTION OUTPUT ;
    USE SIGNAL ;
    SHAPE ABUTMENT ;
    PORT
      LAYER M3_m ;
      RECT 0 476.315 0.07 476.385 ;
    END
  END r0_rd_out[61]
  PIN r0_rd_out[62]
    DIRECTION OUTPUT ;
    USE SIGNAL ;
    SHAPE ABUTMENT ;
    PORT
      LAYER M3_m ;
      RECT 0 478.835 0.07 478.905 ;
    END
  END r0_rd_out[62]
  PIN r0_rd_out[63]
    DIRECTION OUTPUT ;
    USE SIGNAL ;
    SHAPE ABUTMENT ;
    PORT
      LAYER M3_m ;
      RECT 0 481.355 0.07 481.425 ;
    END
  END r0_rd_out[63]
  PIN r0_rd_out[64]
    DIRECTION OUTPUT ;
    USE SIGNAL ;
    SHAPE ABUTMENT ;
    PORT
      LAYER M3_m ;
      RECT 0 483.875 0.07 483.945 ;
    END
  END r0_rd_out[64]
  PIN r0_rd_out[65]
    DIRECTION OUTPUT ;
    USE SIGNAL ;
    SHAPE ABUTMENT ;
    PORT
      LAYER M3_m ;
      RECT 0 486.395 0.07 486.465 ;
    END
  END r0_rd_out[65]
  PIN r0_rd_out[66]
    DIRECTION OUTPUT ;
    USE SIGNAL ;
    SHAPE ABUTMENT ;
    PORT
      LAYER M3_m ;
      RECT 0 488.915 0.07 488.985 ;
    END
  END r0_rd_out[66]
  PIN r0_rd_out[67]
    DIRECTION OUTPUT ;
    USE SIGNAL ;
    SHAPE ABUTMENT ;
    PORT
      LAYER M3_m ;
      RECT 0 491.435 0.07 491.505 ;
    END
  END r0_rd_out[67]
  PIN r0_rd_out[68]
    DIRECTION OUTPUT ;
    USE SIGNAL ;
    SHAPE ABUTMENT ;
    PORT
      LAYER M3_m ;
      RECT 0 493.955 0.07 494.025 ;
    END
  END r0_rd_out[68]
  PIN r0_rd_out[69]
    DIRECTION OUTPUT ;
    USE SIGNAL ;
    SHAPE ABUTMENT ;
    PORT
      LAYER M3_m ;
      RECT 0 496.475 0.07 496.545 ;
    END
  END r0_rd_out[69]
  PIN r0_rd_out[70]
    DIRECTION OUTPUT ;
    USE SIGNAL ;
    SHAPE ABUTMENT ;
    PORT
      LAYER M3_m ;
      RECT 0 498.995 0.07 499.065 ;
    END
  END r0_rd_out[70]
  PIN r0_rd_out[71]
    DIRECTION OUTPUT ;
    USE SIGNAL ;
    SHAPE ABUTMENT ;
    PORT
      LAYER M3_m ;
      RECT 0 501.515 0.07 501.585 ;
    END
  END r0_rd_out[71]
  PIN r0_rd_out[72]
    DIRECTION OUTPUT ;
    USE SIGNAL ;
    SHAPE ABUTMENT ;
    PORT
      LAYER M3_m ;
      RECT 0 504.035 0.07 504.105 ;
    END
  END r0_rd_out[72]
  PIN r0_rd_out[73]
    DIRECTION OUTPUT ;
    USE SIGNAL ;
    SHAPE ABUTMENT ;
    PORT
      LAYER M3_m ;
      RECT 0 506.555 0.07 506.625 ;
    END
  END r0_rd_out[73]
  PIN r0_rd_out[74]
    DIRECTION OUTPUT ;
    USE SIGNAL ;
    SHAPE ABUTMENT ;
    PORT
      LAYER M3_m ;
      RECT 0 509.075 0.07 509.145 ;
    END
  END r0_rd_out[74]
  PIN r0_rd_out[75]
    DIRECTION OUTPUT ;
    USE SIGNAL ;
    SHAPE ABUTMENT ;
    PORT
      LAYER M3_m ;
      RECT 0 511.595 0.07 511.665 ;
    END
  END r0_rd_out[75]
  PIN r0_rd_out[76]
    DIRECTION OUTPUT ;
    USE SIGNAL ;
    SHAPE ABUTMENT ;
    PORT
      LAYER M3_m ;
      RECT 0 514.115 0.07 514.185 ;
    END
  END r0_rd_out[76]
  PIN r0_rd_out[77]
    DIRECTION OUTPUT ;
    USE SIGNAL ;
    SHAPE ABUTMENT ;
    PORT
      LAYER M3_m ;
      RECT 0 516.635 0.07 516.705 ;
    END
  END r0_rd_out[77]
  PIN r0_rd_out[78]
    DIRECTION OUTPUT ;
    USE SIGNAL ;
    SHAPE ABUTMENT ;
    PORT
      LAYER M3_m ;
      RECT 0 519.155 0.07 519.225 ;
    END
  END r0_rd_out[78]
  PIN r0_rd_out[79]
    DIRECTION OUTPUT ;
    USE SIGNAL ;
    SHAPE ABUTMENT ;
    PORT
      LAYER M3_m ;
      RECT 0 521.675 0.07 521.745 ;
    END
  END r0_rd_out[79]
  PIN r0_rd_out[80]
    DIRECTION OUTPUT ;
    USE SIGNAL ;
    SHAPE ABUTMENT ;
    PORT
      LAYER M3_m ;
      RECT 0 524.195 0.07 524.265 ;
    END
  END r0_rd_out[80]
  PIN r0_rd_out[81]
    DIRECTION OUTPUT ;
    USE SIGNAL ;
    SHAPE ABUTMENT ;
    PORT
      LAYER M3_m ;
      RECT 0 526.715 0.07 526.785 ;
    END
  END r0_rd_out[81]
  PIN r0_rd_out[82]
    DIRECTION OUTPUT ;
    USE SIGNAL ;
    SHAPE ABUTMENT ;
    PORT
      LAYER M3_m ;
      RECT 0 529.235 0.07 529.305 ;
    END
  END r0_rd_out[82]
  PIN r0_rd_out[83]
    DIRECTION OUTPUT ;
    USE SIGNAL ;
    SHAPE ABUTMENT ;
    PORT
      LAYER M3_m ;
      RECT 0 531.755 0.07 531.825 ;
    END
  END r0_rd_out[83]
  PIN r0_rd_out[84]
    DIRECTION OUTPUT ;
    USE SIGNAL ;
    SHAPE ABUTMENT ;
    PORT
      LAYER M3_m ;
      RECT 0 534.275 0.07 534.345 ;
    END
  END r0_rd_out[84]
  PIN r0_rd_out[85]
    DIRECTION OUTPUT ;
    USE SIGNAL ;
    SHAPE ABUTMENT ;
    PORT
      LAYER M3_m ;
      RECT 0 536.795 0.07 536.865 ;
    END
  END r0_rd_out[85]
  PIN r0_rd_out[86]
    DIRECTION OUTPUT ;
    USE SIGNAL ;
    SHAPE ABUTMENT ;
    PORT
      LAYER M3_m ;
      RECT 0 539.315 0.07 539.385 ;
    END
  END r0_rd_out[86]
  PIN r0_rd_out[87]
    DIRECTION OUTPUT ;
    USE SIGNAL ;
    SHAPE ABUTMENT ;
    PORT
      LAYER M3_m ;
      RECT 0 541.835 0.07 541.905 ;
    END
  END r0_rd_out[87]
  PIN r0_rd_out[88]
    DIRECTION OUTPUT ;
    USE SIGNAL ;
    SHAPE ABUTMENT ;
    PORT
      LAYER M3_m ;
      RECT 0 544.355 0.07 544.425 ;
    END
  END r0_rd_out[88]
  PIN r0_rd_out[89]
    DIRECTION OUTPUT ;
    USE SIGNAL ;
    SHAPE ABUTMENT ;
    PORT
      LAYER M3_m ;
      RECT 0 546.875 0.07 546.945 ;
    END
  END r0_rd_out[89]
  PIN r0_rd_out[90]
    DIRECTION OUTPUT ;
    USE SIGNAL ;
    SHAPE ABUTMENT ;
    PORT
      LAYER M3_m ;
      RECT 0 549.395 0.07 549.465 ;
    END
  END r0_rd_out[90]
  PIN r0_rd_out[91]
    DIRECTION OUTPUT ;
    USE SIGNAL ;
    SHAPE ABUTMENT ;
    PORT
      LAYER M3_m ;
      RECT 0 551.915 0.07 551.985 ;
    END
  END r0_rd_out[91]
  PIN r0_rd_out[92]
    DIRECTION OUTPUT ;
    USE SIGNAL ;
    SHAPE ABUTMENT ;
    PORT
      LAYER M3_m ;
      RECT 0 554.435 0.07 554.505 ;
    END
  END r0_rd_out[92]
  PIN r0_rd_out[93]
    DIRECTION OUTPUT ;
    USE SIGNAL ;
    SHAPE ABUTMENT ;
    PORT
      LAYER M3_m ;
      RECT 0 556.955 0.07 557.025 ;
    END
  END r0_rd_out[93]
  PIN r0_rd_out[94]
    DIRECTION OUTPUT ;
    USE SIGNAL ;
    SHAPE ABUTMENT ;
    PORT
      LAYER M3_m ;
      RECT 0 559.475 0.07 559.545 ;
    END
  END r0_rd_out[94]
  PIN r0_rd_out[95]
    DIRECTION OUTPUT ;
    USE SIGNAL ;
    SHAPE ABUTMENT ;
    PORT
      LAYER M3_m ;
      RECT 0 561.995 0.07 562.065 ;
    END
  END r0_rd_out[95]
  PIN r0_rd_out[96]
    DIRECTION OUTPUT ;
    USE SIGNAL ;
    SHAPE ABUTMENT ;
    PORT
      LAYER M3_m ;
      RECT 0 564.515 0.07 564.585 ;
    END
  END r0_rd_out[96]
  PIN r0_rd_out[97]
    DIRECTION OUTPUT ;
    USE SIGNAL ;
    SHAPE ABUTMENT ;
    PORT
      LAYER M3_m ;
      RECT 0 567.035 0.07 567.105 ;
    END
  END r0_rd_out[97]
  PIN r0_rd_out[98]
    DIRECTION OUTPUT ;
    USE SIGNAL ;
    SHAPE ABUTMENT ;
    PORT
      LAYER M3_m ;
      RECT 0 569.555 0.07 569.625 ;
    END
  END r0_rd_out[98]
  PIN r0_rd_out[99]
    DIRECTION OUTPUT ;
    USE SIGNAL ;
    SHAPE ABUTMENT ;
    PORT
      LAYER M3_m ;
      RECT 0 572.075 0.07 572.145 ;
    END
  END r0_rd_out[99]
  PIN r0_rd_out[100]
    DIRECTION OUTPUT ;
    USE SIGNAL ;
    SHAPE ABUTMENT ;
    PORT
      LAYER M3_m ;
      RECT 0 574.595 0.07 574.665 ;
    END
  END r0_rd_out[100]
  PIN r0_rd_out[101]
    DIRECTION OUTPUT ;
    USE SIGNAL ;
    SHAPE ABUTMENT ;
    PORT
      LAYER M3_m ;
      RECT 0 577.115 0.07 577.185 ;
    END
  END r0_rd_out[101]
  PIN r0_rd_out[102]
    DIRECTION OUTPUT ;
    USE SIGNAL ;
    SHAPE ABUTMENT ;
    PORT
      LAYER M3_m ;
      RECT 0 579.635 0.07 579.705 ;
    END
  END r0_rd_out[102]
  PIN r0_rd_out[103]
    DIRECTION OUTPUT ;
    USE SIGNAL ;
    SHAPE ABUTMENT ;
    PORT
      LAYER M3_m ;
      RECT 0 582.155 0.07 582.225 ;
    END
  END r0_rd_out[103]
  PIN r0_rd_out[104]
    DIRECTION OUTPUT ;
    USE SIGNAL ;
    SHAPE ABUTMENT ;
    PORT
      LAYER M3_m ;
      RECT 0 584.675 0.07 584.745 ;
    END
  END r0_rd_out[104]
  PIN r0_rd_out[105]
    DIRECTION OUTPUT ;
    USE SIGNAL ;
    SHAPE ABUTMENT ;
    PORT
      LAYER M3_m ;
      RECT 0 587.195 0.07 587.265 ;
    END
  END r0_rd_out[105]
  PIN r0_rd_out[106]
    DIRECTION OUTPUT ;
    USE SIGNAL ;
    SHAPE ABUTMENT ;
    PORT
      LAYER M3_m ;
      RECT 0 589.715 0.07 589.785 ;
    END
  END r0_rd_out[106]
  PIN r0_rd_out[107]
    DIRECTION OUTPUT ;
    USE SIGNAL ;
    SHAPE ABUTMENT ;
    PORT
      LAYER M3_m ;
      RECT 0 592.235 0.07 592.305 ;
    END
  END r0_rd_out[107]
  PIN r0_rd_out[108]
    DIRECTION OUTPUT ;
    USE SIGNAL ;
    SHAPE ABUTMENT ;
    PORT
      LAYER M3_m ;
      RECT 0 594.755 0.07 594.825 ;
    END
  END r0_rd_out[108]
  PIN r0_rd_out[109]
    DIRECTION OUTPUT ;
    USE SIGNAL ;
    SHAPE ABUTMENT ;
    PORT
      LAYER M3_m ;
      RECT 0 597.275 0.07 597.345 ;
    END
  END r0_rd_out[109]
  PIN r0_rd_out[110]
    DIRECTION OUTPUT ;
    USE SIGNAL ;
    SHAPE ABUTMENT ;
    PORT
      LAYER M3_m ;
      RECT 0 599.795 0.07 599.865 ;
    END
  END r0_rd_out[110]
  PIN r0_rd_out[111]
    DIRECTION OUTPUT ;
    USE SIGNAL ;
    SHAPE ABUTMENT ;
    PORT
      LAYER M3_m ;
      RECT 0 602.315 0.07 602.385 ;
    END
  END r0_rd_out[111]
  PIN r0_rd_out[112]
    DIRECTION OUTPUT ;
    USE SIGNAL ;
    SHAPE ABUTMENT ;
    PORT
      LAYER M3_m ;
      RECT 0 604.835 0.07 604.905 ;
    END
  END r0_rd_out[112]
  PIN r0_rd_out[113]
    DIRECTION OUTPUT ;
    USE SIGNAL ;
    SHAPE ABUTMENT ;
    PORT
      LAYER M3_m ;
      RECT 0 607.355 0.07 607.425 ;
    END
  END r0_rd_out[113]
  PIN r0_rd_out[114]
    DIRECTION OUTPUT ;
    USE SIGNAL ;
    SHAPE ABUTMENT ;
    PORT
      LAYER M3_m ;
      RECT 0 609.875 0.07 609.945 ;
    END
  END r0_rd_out[114]
  PIN r0_rd_out[115]
    DIRECTION OUTPUT ;
    USE SIGNAL ;
    SHAPE ABUTMENT ;
    PORT
      LAYER M3_m ;
      RECT 0 612.395 0.07 612.465 ;
    END
  END r0_rd_out[115]
  PIN r0_rd_out[116]
    DIRECTION OUTPUT ;
    USE SIGNAL ;
    SHAPE ABUTMENT ;
    PORT
      LAYER M3_m ;
      RECT 0 614.915 0.07 614.985 ;
    END
  END r0_rd_out[116]
  PIN r0_rd_out[117]
    DIRECTION OUTPUT ;
    USE SIGNAL ;
    SHAPE ABUTMENT ;
    PORT
      LAYER M3_m ;
      RECT 0 617.435 0.07 617.505 ;
    END
  END r0_rd_out[117]
  PIN r0_rd_out[118]
    DIRECTION OUTPUT ;
    USE SIGNAL ;
    SHAPE ABUTMENT ;
    PORT
      LAYER M3_m ;
      RECT 0 619.955 0.07 620.025 ;
    END
  END r0_rd_out[118]
  PIN r0_rd_out[119]
    DIRECTION OUTPUT ;
    USE SIGNAL ;
    SHAPE ABUTMENT ;
    PORT
      LAYER M3_m ;
      RECT 0 622.475 0.07 622.545 ;
    END
  END r0_rd_out[119]
  PIN r0_rd_out[120]
    DIRECTION OUTPUT ;
    USE SIGNAL ;
    SHAPE ABUTMENT ;
    PORT
      LAYER M3_m ;
      RECT 0 624.995 0.07 625.065 ;
    END
  END r0_rd_out[120]
  PIN r0_rd_out[121]
    DIRECTION OUTPUT ;
    USE SIGNAL ;
    SHAPE ABUTMENT ;
    PORT
      LAYER M3_m ;
      RECT 0 627.515 0.07 627.585 ;
    END
  END r0_rd_out[121]
  PIN r0_rd_out[122]
    DIRECTION OUTPUT ;
    USE SIGNAL ;
    SHAPE ABUTMENT ;
    PORT
      LAYER M3_m ;
      RECT 0 630.035 0.07 630.105 ;
    END
  END r0_rd_out[122]
  PIN r0_rd_out[123]
    DIRECTION OUTPUT ;
    USE SIGNAL ;
    SHAPE ABUTMENT ;
    PORT
      LAYER M3_m ;
      RECT 0 632.555 0.07 632.625 ;
    END
  END r0_rd_out[123]
  PIN r0_rd_out[124]
    DIRECTION OUTPUT ;
    USE SIGNAL ;
    SHAPE ABUTMENT ;
    PORT
      LAYER M3_m ;
      RECT 0 635.075 0.07 635.145 ;
    END
  END r0_rd_out[124]
  PIN r0_rd_out[125]
    DIRECTION OUTPUT ;
    USE SIGNAL ;
    SHAPE ABUTMENT ;
    PORT
      LAYER M3_m ;
      RECT 0 637.595 0.07 637.665 ;
    END
  END r0_rd_out[125]
  PIN r0_rd_out[126]
    DIRECTION OUTPUT ;
    USE SIGNAL ;
    SHAPE ABUTMENT ;
    PORT
      LAYER M3_m ;
      RECT 0 640.115 0.07 640.185 ;
    END
  END r0_rd_out[126]
  PIN r0_rd_out[127]
    DIRECTION OUTPUT ;
    USE SIGNAL ;
    SHAPE ABUTMENT ;
    PORT
      LAYER M3_m ;
      RECT 0 642.635 0.07 642.705 ;
    END
  END r0_rd_out[127]
  PIN w0_addr_in[0]
    DIRECTION INPUT ;
    USE SIGNAL ;
    SHAPE ABUTMENT ;
    PORT
      LAYER M3_m ;
      RECT 0 645.155 0.07 645.225 ;
    END
  END w0_addr_in[0]
  PIN w0_addr_in[1]
    DIRECTION INPUT ;
    USE SIGNAL ;
    SHAPE ABUTMENT ;
    PORT
      LAYER M3_m ;
      RECT 0 647.675 0.07 647.745 ;
    END
  END w0_addr_in[1]
  PIN w0_addr_in[2]
    DIRECTION INPUT ;
    USE SIGNAL ;
    SHAPE ABUTMENT ;
    PORT
      LAYER M3_m ;
      RECT 0 650.195 0.07 650.265 ;
    END
  END w0_addr_in[2]
  PIN w0_addr_in[3]
    DIRECTION INPUT ;
    USE SIGNAL ;
    SHAPE ABUTMENT ;
    PORT
      LAYER M3_m ;
      RECT 0 652.715 0.07 652.785 ;
    END
  END w0_addr_in[3]
  PIN w0_addr_in[4]
    DIRECTION INPUT ;
    USE SIGNAL ;
    SHAPE ABUTMENT ;
    PORT
      LAYER M3_m ;
      RECT 0 655.235 0.07 655.305 ;
    END
  END w0_addr_in[4]
  PIN w0_addr_in[5]
    DIRECTION INPUT ;
    USE SIGNAL ;
    SHAPE ABUTMENT ;
    PORT
      LAYER M3_m ;
      RECT 0 657.755 0.07 657.825 ;
    END
  END w0_addr_in[5]
  PIN w0_addr_in[6]
    DIRECTION INPUT ;
    USE SIGNAL ;
    SHAPE ABUTMENT ;
    PORT
      LAYER M3_m ;
      RECT 0 660.275 0.07 660.345 ;
    END
  END w0_addr_in[6]
  PIN w0_addr_in[7]
    DIRECTION INPUT ;
    USE SIGNAL ;
    SHAPE ABUTMENT ;
    PORT
      LAYER M3_m ;
      RECT 0 662.795 0.07 662.865 ;
    END
  END w0_addr_in[7]
  PIN w0_addr_in[8]
    DIRECTION INPUT ;
    USE SIGNAL ;
    SHAPE ABUTMENT ;
    PORT
      LAYER M3_m ;
      RECT 0 665.315 0.07 665.385 ;
    END
  END w0_addr_in[8]
  PIN w0_addr_in[9]
    DIRECTION INPUT ;
    USE SIGNAL ;
    SHAPE ABUTMENT ;
    PORT
      LAYER M3_m ;
      RECT 0 667.835 0.07 667.905 ;
    END
  END w0_addr_in[9]
  PIN w0_addr_in[10]
    DIRECTION INPUT ;
    USE SIGNAL ;
    SHAPE ABUTMENT ;
    PORT
      LAYER M3_m ;
      RECT 0 670.355 0.07 670.425 ;
    END
  END w0_addr_in[10]
  PIN r0_addr_in[0]
    DIRECTION INPUT ;
    USE SIGNAL ;
    SHAPE ABUTMENT ;
    PORT
      LAYER M3_m ;
      RECT 0 672.875 0.07 672.945 ;
    END
  END r0_addr_in[0]
  PIN r0_addr_in[1]
    DIRECTION INPUT ;
    USE SIGNAL ;
    SHAPE ABUTMENT ;
    PORT
      LAYER M3_m ;
      RECT 0 675.395 0.07 675.465 ;
    END
  END r0_addr_in[1]
  PIN r0_addr_in[2]
    DIRECTION INPUT ;
    USE SIGNAL ;
    SHAPE ABUTMENT ;
    PORT
      LAYER M3_m ;
      RECT 0 677.915 0.07 677.985 ;
    END
  END r0_addr_in[2]
  PIN r0_addr_in[3]
    DIRECTION INPUT ;
    USE SIGNAL ;
    SHAPE ABUTMENT ;
    PORT
      LAYER M3_m ;
      RECT 0 680.435 0.07 680.505 ;
    END
  END r0_addr_in[3]
  PIN r0_addr_in[4]
    DIRECTION INPUT ;
    USE SIGNAL ;
    SHAPE ABUTMENT ;
    PORT
      LAYER M3_m ;
      RECT 0 682.955 0.07 683.025 ;
    END
  END r0_addr_in[4]
  PIN r0_addr_in[5]
    DIRECTION INPUT ;
    USE SIGNAL ;
    SHAPE ABUTMENT ;
    PORT
      LAYER M3_m ;
      RECT 0 685.475 0.07 685.545 ;
    END
  END r0_addr_in[5]
  PIN r0_addr_in[6]
    DIRECTION INPUT ;
    USE SIGNAL ;
    SHAPE ABUTMENT ;
    PORT
      LAYER M3_m ;
      RECT 0 687.995 0.07 688.065 ;
    END
  END r0_addr_in[6]
  PIN r0_addr_in[7]
    DIRECTION INPUT ;
    USE SIGNAL ;
    SHAPE ABUTMENT ;
    PORT
      LAYER M3_m ;
      RECT 0 690.515 0.07 690.585 ;
    END
  END r0_addr_in[7]
  PIN r0_addr_in[8]
    DIRECTION INPUT ;
    USE SIGNAL ;
    SHAPE ABUTMENT ;
    PORT
      LAYER M3_m ;
      RECT 0 693.035 0.07 693.105 ;
    END
  END r0_addr_in[8]
  PIN r0_addr_in[9]
    DIRECTION INPUT ;
    USE SIGNAL ;
    SHAPE ABUTMENT ;
    PORT
      LAYER M3_m ;
      RECT 0 695.555 0.07 695.625 ;
    END
  END r0_addr_in[9]
  PIN r0_addr_in[10]
    DIRECTION INPUT ;
    USE SIGNAL ;
    SHAPE ABUTMENT ;
    PORT
      LAYER M3_m ;
      RECT 0 698.075 0.07 698.145 ;
    END
  END r0_addr_in[10]
  PIN w0_we_in
    DIRECTION INPUT ;
    USE SIGNAL ;
    SHAPE ABUTMENT ;
    PORT
      LAYER M3_m ;
      RECT 0 700.595 0.07 700.665 ;
    END
  END w0_we_in
  PIN w0_ce_in
    DIRECTION INPUT ;
    USE SIGNAL ;
    SHAPE ABUTMENT ;
    PORT
      LAYER M3_m ;
      RECT 0 703.115 0.07 703.185 ;
    END
  END w0_ce_in
  PIN w0_clk
    DIRECTION INPUT ;
    USE SIGNAL ;
    SHAPE ABUTMENT ;
    PORT
      LAYER M3_m ;
      RECT 0 705.635 0.07 705.705 ;
    END
  END w0_clk
  PIN r0_ce_in
    DIRECTION INPUT ;
    USE SIGNAL ;
    SHAPE ABUTMENT ;
    PORT
      LAYER M3_m ;
      RECT 0 708.155 0.07 708.225 ;
    END
  END r0_ce_in
  PIN r0_clk
    DIRECTION INPUT ;
    USE SIGNAL ;
    SHAPE ABUTMENT ;
    PORT
      LAYER M3_m ;
      RECT 0 710.675 0.07 710.745 ;
    END
  END r0_clk
  PIN VSS
    DIRECTION INOUT ;
    USE GROUND ;
    PORT
      LAYER M4_m ;
      RECT 1 0.84 1.28 725.76 ;
      RECT 3.24 0.84 3.52 725.76 ;
      RECT 5.48 0.84 5.76 725.76 ;
      RECT 7.72 0.84 8 725.76 ;
      RECT 9.96 0.84 10.24 725.76 ;
      RECT 12.2 0.84 12.48 725.76 ;
      RECT 14.44 0.84 14.72 725.76 ;
      RECT 16.68 0.84 16.96 725.76 ;
      RECT 18.92 0.84 19.2 725.76 ;
      RECT 21.16 0.84 21.44 725.76 ;
      RECT 23.4 0.84 23.68 725.76 ;
      RECT 25.64 0.84 25.92 725.76 ;
      RECT 27.88 0.84 28.16 725.76 ;
      RECT 30.12 0.84 30.4 725.76 ;
      RECT 32.36 0.84 32.64 725.76 ;
      RECT 34.6 0.84 34.88 725.76 ;
      RECT 36.84 0.84 37.12 725.76 ;
      RECT 39.08 0.84 39.36 725.76 ;
      RECT 41.32 0.84 41.6 725.76 ;
      RECT 43.56 0.84 43.84 725.76 ;
      RECT 45.8 0.84 46.08 725.76 ;
      RECT 48.04 0.84 48.32 725.76 ;
      RECT 50.28 0.84 50.56 725.76 ;
      RECT 52.52 0.84 52.8 725.76 ;
      RECT 54.76 0.84 55.04 725.76 ;
      RECT 57 0.84 57.28 725.76 ;
      RECT 59.24 0.84 59.52 725.76 ;
      RECT 61.48 0.84 61.76 725.76 ;
      RECT 63.72 0.84 64 725.76 ;
      RECT 65.96 0.84 66.24 725.76 ;
      RECT 68.2 0.84 68.48 725.76 ;
      RECT 70.44 0.84 70.72 725.76 ;
      RECT 72.68 0.84 72.96 725.76 ;
      RECT 74.92 0.84 75.2 725.76 ;
      RECT 77.16 0.84 77.44 725.76 ;
      RECT 79.4 0.84 79.68 725.76 ;
      RECT 81.64 0.84 81.92 725.76 ;
      RECT 83.88 0.84 84.16 725.76 ;
      RECT 86.12 0.84 86.4 725.76 ;
      RECT 88.36 0.84 88.64 725.76 ;
      RECT 90.6 0.84 90.88 725.76 ;
      RECT 92.84 0.84 93.12 725.76 ;
      RECT 95.08 0.84 95.36 725.76 ;
      RECT 97.32 0.84 97.6 725.76 ;
      RECT 99.56 0.84 99.84 725.76 ;
      RECT 101.8 0.84 102.08 725.76 ;
      RECT 104.04 0.84 104.32 725.76 ;
      RECT 106.28 0.84 106.56 725.76 ;
      RECT 108.52 0.84 108.8 725.76 ;
      RECT 110.76 0.84 111.04 725.76 ;
      RECT 113 0.84 113.28 725.76 ;
      RECT 115.24 0.84 115.52 725.76 ;
      RECT 117.48 0.84 117.76 725.76 ;
      RECT 119.72 0.84 120 725.76 ;
      RECT 121.96 0.84 122.24 725.76 ;
      RECT 124.2 0.84 124.48 725.76 ;
      RECT 126.44 0.84 126.72 725.76 ;
      RECT 128.68 0.84 128.96 725.76 ;
      RECT 130.92 0.84 131.2 725.76 ;
      RECT 133.16 0.84 133.44 725.76 ;
      RECT 135.4 0.84 135.68 725.76 ;
      RECT 137.64 0.84 137.92 725.76 ;
      RECT 139.88 0.84 140.16 725.76 ;
      RECT 142.12 0.84 142.4 725.76 ;
      RECT 144.36 0.84 144.64 725.76 ;
      RECT 146.6 0.84 146.88 725.76 ;
      RECT 148.84 0.84 149.12 725.76 ;
      RECT 151.08 0.84 151.36 725.76 ;
      RECT 153.32 0.84 153.6 725.76 ;
      RECT 155.56 0.84 155.84 725.76 ;
      RECT 157.8 0.84 158.08 725.76 ;
      RECT 160.04 0.84 160.32 725.76 ;
      RECT 162.28 0.84 162.56 725.76 ;
      RECT 164.52 0.84 164.8 725.76 ;
      RECT 166.76 0.84 167.04 725.76 ;
      RECT 169 0.84 169.28 725.76 ;
      RECT 171.24 0.84 171.52 725.76 ;
      RECT 173.48 0.84 173.76 725.76 ;
      RECT 175.72 0.84 176 725.76 ;
      RECT 177.96 0.84 178.24 725.76 ;
      RECT 180.2 0.84 180.48 725.76 ;
      RECT 182.44 0.84 182.72 725.76 ;
      RECT 184.68 0.84 184.96 725.76 ;
      RECT 186.92 0.84 187.2 725.76 ;
      RECT 189.16 0.84 189.44 725.76 ;
      RECT 191.4 0.84 191.68 725.76 ;
      RECT 193.64 0.84 193.92 725.76 ;
      RECT 195.88 0.84 196.16 725.76 ;
      RECT 198.12 0.84 198.4 725.76 ;
      RECT 200.36 0.84 200.64 725.76 ;
      RECT 202.6 0.84 202.88 725.76 ;
      RECT 204.84 0.84 205.12 725.76 ;
      RECT 207.08 0.84 207.36 725.76 ;
      RECT 209.32 0.84 209.6 725.76 ;
      RECT 211.56 0.84 211.84 725.76 ;
      RECT 213.8 0.84 214.08 725.76 ;
      RECT 216.04 0.84 216.32 725.76 ;
      RECT 218.28 0.84 218.56 725.76 ;
      RECT 220.52 0.84 220.8 725.76 ;
      RECT 222.76 0.84 223.04 725.76 ;
      RECT 225 0.84 225.28 725.76 ;
      RECT 227.24 0.84 227.52 725.76 ;
      RECT 229.48 0.84 229.76 725.76 ;
      RECT 231.72 0.84 232 725.76 ;
      RECT 233.96 0.84 234.24 725.76 ;
      RECT 236.2 0.84 236.48 725.76 ;
      RECT 238.44 0.84 238.72 725.76 ;
      RECT 240.68 0.84 240.96 725.76 ;
      RECT 242.92 0.84 243.2 725.76 ;
      RECT 245.16 0.84 245.44 725.76 ;
      RECT 247.4 0.84 247.68 725.76 ;
      RECT 249.64 0.84 249.92 725.76 ;
      RECT 251.88 0.84 252.16 725.76 ;
      RECT 254.12 0.84 254.4 725.76 ;
      RECT 256.36 0.84 256.64 725.76 ;
      RECT 258.6 0.84 258.88 725.76 ;
      RECT 260.84 0.84 261.12 725.76 ;
      RECT 263.08 0.84 263.36 725.76 ;
      RECT 265.32 0.84 265.6 725.76 ;
      RECT 267.56 0.84 267.84 725.76 ;
      RECT 269.8 0.84 270.08 725.76 ;
      RECT 272.04 0.84 272.32 725.76 ;
      RECT 274.28 0.84 274.56 725.76 ;
      RECT 276.52 0.84 276.8 725.76 ;
      RECT 278.76 0.84 279.04 725.76 ;
      RECT 281 0.84 281.28 725.76 ;
      RECT 283.24 0.84 283.52 725.76 ;
      RECT 285.48 0.84 285.76 725.76 ;
      RECT 287.72 0.84 288 725.76 ;
      RECT 289.96 0.84 290.24 725.76 ;
      RECT 292.2 0.84 292.48 725.76 ;
      RECT 294.44 0.84 294.72 725.76 ;
      RECT 296.68 0.84 296.96 725.76 ;
      RECT 298.92 0.84 299.2 725.76 ;
      RECT 301.16 0.84 301.44 725.76 ;
      RECT 303.4 0.84 303.68 725.76 ;
      RECT 305.64 0.84 305.92 725.76 ;
      RECT 307.88 0.84 308.16 725.76 ;
      RECT 310.12 0.84 310.4 725.76 ;
      RECT 312.36 0.84 312.64 725.76 ;
      RECT 314.6 0.84 314.88 725.76 ;
      RECT 316.84 0.84 317.12 725.76 ;
      RECT 319.08 0.84 319.36 725.76 ;
      RECT 321.32 0.84 321.6 725.76 ;
      RECT 323.56 0.84 323.84 725.76 ;
      RECT 325.8 0.84 326.08 725.76 ;
      RECT 328.04 0.84 328.32 725.76 ;
      RECT 330.28 0.84 330.56 725.76 ;
      RECT 332.52 0.84 332.8 725.76 ;
      RECT 334.76 0.84 335.04 725.76 ;
      RECT 337 0.84 337.28 725.76 ;
      RECT 339.24 0.84 339.52 725.76 ;
      RECT 341.48 0.84 341.76 725.76 ;
      RECT 343.72 0.84 344 725.76 ;
      RECT 345.96 0.84 346.24 725.76 ;
      RECT 348.2 0.84 348.48 725.76 ;
      RECT 350.44 0.84 350.72 725.76 ;
      RECT 352.68 0.84 352.96 725.76 ;
      RECT 354.92 0.84 355.2 725.76 ;
      RECT 357.16 0.84 357.44 725.76 ;
      RECT 359.4 0.84 359.68 725.76 ;
      RECT 361.64 0.84 361.92 725.76 ;
      RECT 363.88 0.84 364.16 725.76 ;
      RECT 366.12 0.84 366.4 725.76 ;
      RECT 368.36 0.84 368.64 725.76 ;
      RECT 370.6 0.84 370.88 725.76 ;
      RECT 372.84 0.84 373.12 725.76 ;
      RECT 375.08 0.84 375.36 725.76 ;
      RECT 377.32 0.84 377.6 725.76 ;
      RECT 379.56 0.84 379.84 725.76 ;
      RECT 381.8 0.84 382.08 725.76 ;
      RECT 384.04 0.84 384.32 725.76 ;
      RECT 386.28 0.84 386.56 725.76 ;
      RECT 388.52 0.84 388.8 725.76 ;
      RECT 390.76 0.84 391.04 725.76 ;
      RECT 393 0.84 393.28 725.76 ;
      RECT 395.24 0.84 395.52 725.76 ;
      RECT 397.48 0.84 397.76 725.76 ;
      RECT 399.72 0.84 400 725.76 ;
      RECT 401.96 0.84 402.24 725.76 ;
      RECT 404.2 0.84 404.48 725.76 ;
      RECT 406.44 0.84 406.72 725.76 ;
      RECT 408.68 0.84 408.96 725.76 ;
      RECT 410.92 0.84 411.2 725.76 ;
      RECT 413.16 0.84 413.44 725.76 ;
      RECT 415.4 0.84 415.68 725.76 ;
      RECT 417.64 0.84 417.92 725.76 ;
      RECT 419.88 0.84 420.16 725.76 ;
      RECT 422.12 0.84 422.4 725.76 ;
      RECT 424.36 0.84 424.64 725.76 ;
      RECT 426.6 0.84 426.88 725.76 ;
      RECT 428.84 0.84 429.12 725.76 ;
      RECT 431.08 0.84 431.36 725.76 ;
      RECT 433.32 0.84 433.6 725.76 ;
      RECT 435.56 0.84 435.84 725.76 ;
      RECT 437.8 0.84 438.08 725.76 ;
      RECT 440.04 0.84 440.32 725.76 ;
      RECT 442.28 0.84 442.56 725.76 ;
      RECT 444.52 0.84 444.8 725.76 ;
      RECT 446.76 0.84 447.04 725.76 ;
      RECT 449 0.84 449.28 725.76 ;
      RECT 451.24 0.84 451.52 725.76 ;
      RECT 453.48 0.84 453.76 725.76 ;
      RECT 455.72 0.84 456 725.76 ;
      RECT 457.96 0.84 458.24 725.76 ;
      RECT 460.2 0.84 460.48 725.76 ;
      RECT 462.44 0.84 462.72 725.76 ;
      RECT 464.68 0.84 464.96 725.76 ;
      RECT 466.92 0.84 467.2 725.76 ;
      RECT 469.16 0.84 469.44 725.76 ;
      RECT 471.4 0.84 471.68 725.76 ;
      RECT 473.64 0.84 473.92 725.76 ;
      RECT 475.88 0.84 476.16 725.76 ;
      RECT 478.12 0.84 478.4 725.76 ;
      RECT 480.36 0.84 480.64 725.76 ;
      RECT 482.6 0.84 482.88 725.76 ;
      RECT 484.84 0.84 485.12 725.76 ;
      RECT 487.08 0.84 487.36 725.76 ;
      RECT 489.32 0.84 489.6 725.76 ;
      RECT 491.56 0.84 491.84 725.76 ;
      RECT 493.8 0.84 494.08 725.76 ;
      RECT 496.04 0.84 496.32 725.76 ;
      RECT 498.28 0.84 498.56 725.76 ;
      RECT 500.52 0.84 500.8 725.76 ;
      RECT 502.76 0.84 503.04 725.76 ;
      RECT 505 0.84 505.28 725.76 ;
      RECT 507.24 0.84 507.52 725.76 ;
      RECT 509.48 0.84 509.76 725.76 ;
      RECT 511.72 0.84 512 725.76 ;
      RECT 513.96 0.84 514.24 725.76 ;
      RECT 516.2 0.84 516.48 725.76 ;
      RECT 518.44 0.84 518.72 725.76 ;
      RECT 520.68 0.84 520.96 725.76 ;
      RECT 522.92 0.84 523.2 725.76 ;
      RECT 525.16 0.84 525.44 725.76 ;
      RECT 527.4 0.84 527.68 725.76 ;
      RECT 529.64 0.84 529.92 725.76 ;
      RECT 531.88 0.84 532.16 725.76 ;
      RECT 534.12 0.84 534.4 725.76 ;
      RECT 536.36 0.84 536.64 725.76 ;
      RECT 538.6 0.84 538.88 725.76 ;
      RECT 540.84 0.84 541.12 725.76 ;
      RECT 543.08 0.84 543.36 725.76 ;
      RECT 545.32 0.84 545.6 725.76 ;
      RECT 547.56 0.84 547.84 725.76 ;
      RECT 549.8 0.84 550.08 725.76 ;
      RECT 552.04 0.84 552.32 725.76 ;
      RECT 554.28 0.84 554.56 725.76 ;
      RECT 556.52 0.84 556.8 725.76 ;
      RECT 558.76 0.84 559.04 725.76 ;
      RECT 561 0.84 561.28 725.76 ;
      RECT 563.24 0.84 563.52 725.76 ;
      RECT 565.48 0.84 565.76 725.76 ;
      RECT 567.72 0.84 568 725.76 ;
      RECT 569.96 0.84 570.24 725.76 ;
      RECT 572.2 0.84 572.48 725.76 ;
      RECT 574.44 0.84 574.72 725.76 ;
      RECT 576.68 0.84 576.96 725.76 ;
      RECT 578.92 0.84 579.2 725.76 ;
      RECT 581.16 0.84 581.44 725.76 ;
      RECT 583.4 0.84 583.68 725.76 ;
      RECT 585.64 0.84 585.92 725.76 ;
      RECT 587.88 0.84 588.16 725.76 ;
      RECT 590.12 0.84 590.4 725.76 ;
      RECT 592.36 0.84 592.64 725.76 ;
    END
  END VSS
  PIN VDD
    DIRECTION INOUT ;
    USE POWER ;
    PORT
      LAYER M4_m ;
      RECT 2.12 0.84 2.4 725.76 ;
      RECT 4.36 0.84 4.64 725.76 ;
      RECT 6.6 0.84 6.88 725.76 ;
      RECT 8.84 0.84 9.12 725.76 ;
      RECT 11.08 0.84 11.36 725.76 ;
      RECT 13.32 0.84 13.6 725.76 ;
      RECT 15.56 0.84 15.84 725.76 ;
      RECT 17.8 0.84 18.08 725.76 ;
      RECT 20.04 0.84 20.32 725.76 ;
      RECT 22.28 0.84 22.56 725.76 ;
      RECT 24.52 0.84 24.8 725.76 ;
      RECT 26.76 0.84 27.04 725.76 ;
      RECT 29 0.84 29.28 725.76 ;
      RECT 31.24 0.84 31.52 725.76 ;
      RECT 33.48 0.84 33.76 725.76 ;
      RECT 35.72 0.84 36 725.76 ;
      RECT 37.96 0.84 38.24 725.76 ;
      RECT 40.2 0.84 40.48 725.76 ;
      RECT 42.44 0.84 42.72 725.76 ;
      RECT 44.68 0.84 44.96 725.76 ;
      RECT 46.92 0.84 47.2 725.76 ;
      RECT 49.16 0.84 49.44 725.76 ;
      RECT 51.4 0.84 51.68 725.76 ;
      RECT 53.64 0.84 53.92 725.76 ;
      RECT 55.88 0.84 56.16 725.76 ;
      RECT 58.12 0.84 58.4 725.76 ;
      RECT 60.36 0.84 60.64 725.76 ;
      RECT 62.6 0.84 62.88 725.76 ;
      RECT 64.84 0.84 65.12 725.76 ;
      RECT 67.08 0.84 67.36 725.76 ;
      RECT 69.32 0.84 69.6 725.76 ;
      RECT 71.56 0.84 71.84 725.76 ;
      RECT 73.8 0.84 74.08 725.76 ;
      RECT 76.04 0.84 76.32 725.76 ;
      RECT 78.28 0.84 78.56 725.76 ;
      RECT 80.52 0.84 80.8 725.76 ;
      RECT 82.76 0.84 83.04 725.76 ;
      RECT 85 0.84 85.28 725.76 ;
      RECT 87.24 0.84 87.52 725.76 ;
      RECT 89.48 0.84 89.76 725.76 ;
      RECT 91.72 0.84 92 725.76 ;
      RECT 93.96 0.84 94.24 725.76 ;
      RECT 96.2 0.84 96.48 725.76 ;
      RECT 98.44 0.84 98.72 725.76 ;
      RECT 100.68 0.84 100.96 725.76 ;
      RECT 102.92 0.84 103.2 725.76 ;
      RECT 105.16 0.84 105.44 725.76 ;
      RECT 107.4 0.84 107.68 725.76 ;
      RECT 109.64 0.84 109.92 725.76 ;
      RECT 111.88 0.84 112.16 725.76 ;
      RECT 114.12 0.84 114.4 725.76 ;
      RECT 116.36 0.84 116.64 725.76 ;
      RECT 118.6 0.84 118.88 725.76 ;
      RECT 120.84 0.84 121.12 725.76 ;
      RECT 123.08 0.84 123.36 725.76 ;
      RECT 125.32 0.84 125.6 725.76 ;
      RECT 127.56 0.84 127.84 725.76 ;
      RECT 129.8 0.84 130.08 725.76 ;
      RECT 132.04 0.84 132.32 725.76 ;
      RECT 134.28 0.84 134.56 725.76 ;
      RECT 136.52 0.84 136.8 725.76 ;
      RECT 138.76 0.84 139.04 725.76 ;
      RECT 141 0.84 141.28 725.76 ;
      RECT 143.24 0.84 143.52 725.76 ;
      RECT 145.48 0.84 145.76 725.76 ;
      RECT 147.72 0.84 148 725.76 ;
      RECT 149.96 0.84 150.24 725.76 ;
      RECT 152.2 0.84 152.48 725.76 ;
      RECT 154.44 0.84 154.72 725.76 ;
      RECT 156.68 0.84 156.96 725.76 ;
      RECT 158.92 0.84 159.2 725.76 ;
      RECT 161.16 0.84 161.44 725.76 ;
      RECT 163.4 0.84 163.68 725.76 ;
      RECT 165.64 0.84 165.92 725.76 ;
      RECT 167.88 0.84 168.16 725.76 ;
      RECT 170.12 0.84 170.4 725.76 ;
      RECT 172.36 0.84 172.64 725.76 ;
      RECT 174.6 0.84 174.88 725.76 ;
      RECT 176.84 0.84 177.12 725.76 ;
      RECT 179.08 0.84 179.36 725.76 ;
      RECT 181.32 0.84 181.6 725.76 ;
      RECT 183.56 0.84 183.84 725.76 ;
      RECT 185.8 0.84 186.08 725.76 ;
      RECT 188.04 0.84 188.32 725.76 ;
      RECT 190.28 0.84 190.56 725.76 ;
      RECT 192.52 0.84 192.8 725.76 ;
      RECT 194.76 0.84 195.04 725.76 ;
      RECT 197 0.84 197.28 725.76 ;
      RECT 199.24 0.84 199.52 725.76 ;
      RECT 201.48 0.84 201.76 725.76 ;
      RECT 203.72 0.84 204 725.76 ;
      RECT 205.96 0.84 206.24 725.76 ;
      RECT 208.2 0.84 208.48 725.76 ;
      RECT 210.44 0.84 210.72 725.76 ;
      RECT 212.68 0.84 212.96 725.76 ;
      RECT 214.92 0.84 215.2 725.76 ;
      RECT 217.16 0.84 217.44 725.76 ;
      RECT 219.4 0.84 219.68 725.76 ;
      RECT 221.64 0.84 221.92 725.76 ;
      RECT 223.88 0.84 224.16 725.76 ;
      RECT 226.12 0.84 226.4 725.76 ;
      RECT 228.36 0.84 228.64 725.76 ;
      RECT 230.6 0.84 230.88 725.76 ;
      RECT 232.84 0.84 233.12 725.76 ;
      RECT 235.08 0.84 235.36 725.76 ;
      RECT 237.32 0.84 237.6 725.76 ;
      RECT 239.56 0.84 239.84 725.76 ;
      RECT 241.8 0.84 242.08 725.76 ;
      RECT 244.04 0.84 244.32 725.76 ;
      RECT 246.28 0.84 246.56 725.76 ;
      RECT 248.52 0.84 248.8 725.76 ;
      RECT 250.76 0.84 251.04 725.76 ;
      RECT 253 0.84 253.28 725.76 ;
      RECT 255.24 0.84 255.52 725.76 ;
      RECT 257.48 0.84 257.76 725.76 ;
      RECT 259.72 0.84 260 725.76 ;
      RECT 261.96 0.84 262.24 725.76 ;
      RECT 264.2 0.84 264.48 725.76 ;
      RECT 266.44 0.84 266.72 725.76 ;
      RECT 268.68 0.84 268.96 725.76 ;
      RECT 270.92 0.84 271.2 725.76 ;
      RECT 273.16 0.84 273.44 725.76 ;
      RECT 275.4 0.84 275.68 725.76 ;
      RECT 277.64 0.84 277.92 725.76 ;
      RECT 279.88 0.84 280.16 725.76 ;
      RECT 282.12 0.84 282.4 725.76 ;
      RECT 284.36 0.84 284.64 725.76 ;
      RECT 286.6 0.84 286.88 725.76 ;
      RECT 288.84 0.84 289.12 725.76 ;
      RECT 291.08 0.84 291.36 725.76 ;
      RECT 293.32 0.84 293.6 725.76 ;
      RECT 295.56 0.84 295.84 725.76 ;
      RECT 297.8 0.84 298.08 725.76 ;
      RECT 300.04 0.84 300.32 725.76 ;
      RECT 302.28 0.84 302.56 725.76 ;
      RECT 304.52 0.84 304.8 725.76 ;
      RECT 306.76 0.84 307.04 725.76 ;
      RECT 309 0.84 309.28 725.76 ;
      RECT 311.24 0.84 311.52 725.76 ;
      RECT 313.48 0.84 313.76 725.76 ;
      RECT 315.72 0.84 316 725.76 ;
      RECT 317.96 0.84 318.24 725.76 ;
      RECT 320.2 0.84 320.48 725.76 ;
      RECT 322.44 0.84 322.72 725.76 ;
      RECT 324.68 0.84 324.96 725.76 ;
      RECT 326.92 0.84 327.2 725.76 ;
      RECT 329.16 0.84 329.44 725.76 ;
      RECT 331.4 0.84 331.68 725.76 ;
      RECT 333.64 0.84 333.92 725.76 ;
      RECT 335.88 0.84 336.16 725.76 ;
      RECT 338.12 0.84 338.4 725.76 ;
      RECT 340.36 0.84 340.64 725.76 ;
      RECT 342.6 0.84 342.88 725.76 ;
      RECT 344.84 0.84 345.12 725.76 ;
      RECT 347.08 0.84 347.36 725.76 ;
      RECT 349.32 0.84 349.6 725.76 ;
      RECT 351.56 0.84 351.84 725.76 ;
      RECT 353.8 0.84 354.08 725.76 ;
      RECT 356.04 0.84 356.32 725.76 ;
      RECT 358.28 0.84 358.56 725.76 ;
      RECT 360.52 0.84 360.8 725.76 ;
      RECT 362.76 0.84 363.04 725.76 ;
      RECT 365 0.84 365.28 725.76 ;
      RECT 367.24 0.84 367.52 725.76 ;
      RECT 369.48 0.84 369.76 725.76 ;
      RECT 371.72 0.84 372 725.76 ;
      RECT 373.96 0.84 374.24 725.76 ;
      RECT 376.2 0.84 376.48 725.76 ;
      RECT 378.44 0.84 378.72 725.76 ;
      RECT 380.68 0.84 380.96 725.76 ;
      RECT 382.92 0.84 383.2 725.76 ;
      RECT 385.16 0.84 385.44 725.76 ;
      RECT 387.4 0.84 387.68 725.76 ;
      RECT 389.64 0.84 389.92 725.76 ;
      RECT 391.88 0.84 392.16 725.76 ;
      RECT 394.12 0.84 394.4 725.76 ;
      RECT 396.36 0.84 396.64 725.76 ;
      RECT 398.6 0.84 398.88 725.76 ;
      RECT 400.84 0.84 401.12 725.76 ;
      RECT 403.08 0.84 403.36 725.76 ;
      RECT 405.32 0.84 405.6 725.76 ;
      RECT 407.56 0.84 407.84 725.76 ;
      RECT 409.8 0.84 410.08 725.76 ;
      RECT 412.04 0.84 412.32 725.76 ;
      RECT 414.28 0.84 414.56 725.76 ;
      RECT 416.52 0.84 416.8 725.76 ;
      RECT 418.76 0.84 419.04 725.76 ;
      RECT 421 0.84 421.28 725.76 ;
      RECT 423.24 0.84 423.52 725.76 ;
      RECT 425.48 0.84 425.76 725.76 ;
      RECT 427.72 0.84 428 725.76 ;
      RECT 429.96 0.84 430.24 725.76 ;
      RECT 432.2 0.84 432.48 725.76 ;
      RECT 434.44 0.84 434.72 725.76 ;
      RECT 436.68 0.84 436.96 725.76 ;
      RECT 438.92 0.84 439.2 725.76 ;
      RECT 441.16 0.84 441.44 725.76 ;
      RECT 443.4 0.84 443.68 725.76 ;
      RECT 445.64 0.84 445.92 725.76 ;
      RECT 447.88 0.84 448.16 725.76 ;
      RECT 450.12 0.84 450.4 725.76 ;
      RECT 452.36 0.84 452.64 725.76 ;
      RECT 454.6 0.84 454.88 725.76 ;
      RECT 456.84 0.84 457.12 725.76 ;
      RECT 459.08 0.84 459.36 725.76 ;
      RECT 461.32 0.84 461.6 725.76 ;
      RECT 463.56 0.84 463.84 725.76 ;
      RECT 465.8 0.84 466.08 725.76 ;
      RECT 468.04 0.84 468.32 725.76 ;
      RECT 470.28 0.84 470.56 725.76 ;
      RECT 472.52 0.84 472.8 725.76 ;
      RECT 474.76 0.84 475.04 725.76 ;
      RECT 477 0.84 477.28 725.76 ;
      RECT 479.24 0.84 479.52 725.76 ;
      RECT 481.48 0.84 481.76 725.76 ;
      RECT 483.72 0.84 484 725.76 ;
      RECT 485.96 0.84 486.24 725.76 ;
      RECT 488.2 0.84 488.48 725.76 ;
      RECT 490.44 0.84 490.72 725.76 ;
      RECT 492.68 0.84 492.96 725.76 ;
      RECT 494.92 0.84 495.2 725.76 ;
      RECT 497.16 0.84 497.44 725.76 ;
      RECT 499.4 0.84 499.68 725.76 ;
      RECT 501.64 0.84 501.92 725.76 ;
      RECT 503.88 0.84 504.16 725.76 ;
      RECT 506.12 0.84 506.4 725.76 ;
      RECT 508.36 0.84 508.64 725.76 ;
      RECT 510.6 0.84 510.88 725.76 ;
      RECT 512.84 0.84 513.12 725.76 ;
      RECT 515.08 0.84 515.36 725.76 ;
      RECT 517.32 0.84 517.6 725.76 ;
      RECT 519.56 0.84 519.84 725.76 ;
      RECT 521.8 0.84 522.08 725.76 ;
      RECT 524.04 0.84 524.32 725.76 ;
      RECT 526.28 0.84 526.56 725.76 ;
      RECT 528.52 0.84 528.8 725.76 ;
      RECT 530.76 0.84 531.04 725.76 ;
      RECT 533 0.84 533.28 725.76 ;
      RECT 535.24 0.84 535.52 725.76 ;
      RECT 537.48 0.84 537.76 725.76 ;
      RECT 539.72 0.84 540 725.76 ;
      RECT 541.96 0.84 542.24 725.76 ;
      RECT 544.2 0.84 544.48 725.76 ;
      RECT 546.44 0.84 546.72 725.76 ;
      RECT 548.68 0.84 548.96 725.76 ;
      RECT 550.92 0.84 551.2 725.76 ;
      RECT 553.16 0.84 553.44 725.76 ;
      RECT 555.4 0.84 555.68 725.76 ;
      RECT 557.64 0.84 557.92 725.76 ;
      RECT 559.88 0.84 560.16 725.76 ;
      RECT 562.12 0.84 562.4 725.76 ;
      RECT 564.36 0.84 564.64 725.76 ;
      RECT 566.6 0.84 566.88 725.76 ;
      RECT 568.84 0.84 569.12 725.76 ;
      RECT 571.08 0.84 571.36 725.76 ;
      RECT 573.32 0.84 573.6 725.76 ;
      RECT 575.56 0.84 575.84 725.76 ;
      RECT 577.8 0.84 578.08 725.76 ;
      RECT 580.04 0.84 580.32 725.76 ;
      RECT 582.28 0.84 582.56 725.76 ;
      RECT 584.52 0.84 584.8 725.76 ;
      RECT 586.76 0.84 587.04 725.76 ;
      RECT 589 0.84 589.28 725.76 ;
      RECT 591.24 0.84 591.52 725.76 ;
      RECT 593.48 0.84 593.76 725.76 ;
    END
  END VDD
  OBS
    LAYER M1_m ;
    RECT 0 0 594.32 726.6 ;
    LAYER M2_m ;
    RECT 0 0 594.32 726.6 ;
  END
END ht45_leon3vtabus_tensorFile_0_2_ext_upper

END LIBRARY
